VERSION 5.8 ;
BUSBITCHARS "[]" ;
DIVIDERCHAR "/" ;
 
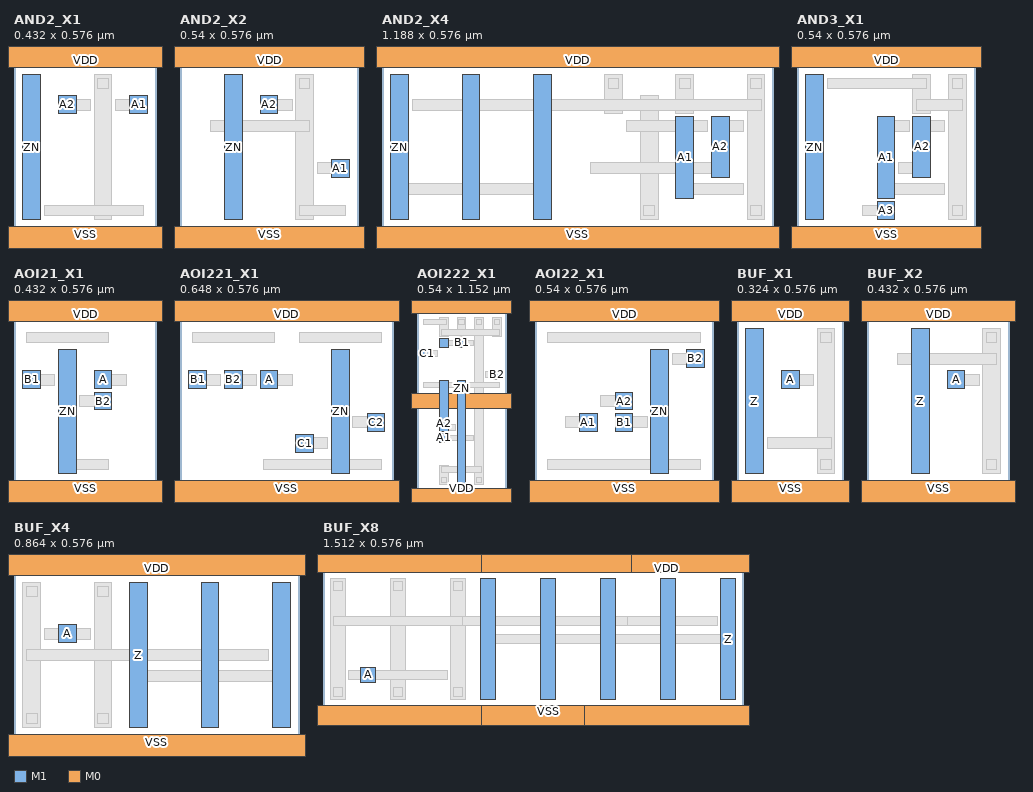
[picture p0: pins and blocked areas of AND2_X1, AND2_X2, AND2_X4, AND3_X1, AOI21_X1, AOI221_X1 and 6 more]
MACRO AND2_X1
  CLASS CORE ;
  FOREIGN AND2_X1 0 0 ;
  SIZE 0.432 BY 0.576 ;
  ORIGIN 0.0 0.0 ;
  SYMMETRY X Y ;
  PIN A1
    DIRECTION INPUT ;
    USE SIGNAL ;
    ANTENNAGATEAREA 0.005280 ;
    PORT
      LAYER M1 ;
        RECT 0.351 0.389 0.405 0.443 ;
    END
  END A1
  PIN A2
    DIRECTION INPUT ;
    USE SIGNAL ;
    ANTENNAGATEAREA 0.005280 ;
    PORT
      LAYER M1 ;
        RECT 0.135 0.389 0.189 0.443 ;
    END
  END A2
  PIN ZN
    DIRECTION OUTPUT ;
    USE SIGNAL ;
    ANTENNADIFFAREA 0.02064 ;
    PORT
      LAYER M1 ;
        RECT 0.027 0.069 0.081 0.507 ;
    END
  END ZN
  PIN VDD
    DIRECTION INOUT ;
    USE POWER ;
    PORT
      LAYER M0 ;
        RECT -0.031 0.528 0.463 0.624 ;
    END
  END VDD
  PIN VSS
    DIRECTION INOUT ;
    USE GROUND ;
    PORT
      LAYER M0 ;
        RECT -0.031 -0.048 0.463 0.048 ;
    END
  END VSS
  OBS
    LAYER M1 ;
      RECT 0.243 0.069 0.297 0.507 ;
    LAYER M0 ;
      RECT 0.092 0.08 0.394 0.112 ;
      RECT 0.254 0.464 0.286 0.496 ;
      RECT 0.308 0.4 0.394 0.432 ;
      RECT 0.146 0.4 0.232 0.432 ;
      RECT 0.038 0.464 0.07 0.496 ;
      RECT 0.038 0.08 0.07 0.112 ;
  END
END AND2_X1

MACRO AND2_X2
  CLASS CORE ;
  FOREIGN AND2_X2 0 0 ;
  SIZE 0.54 BY 0.576 ;
  ORIGIN 0.0 0.0 ;
  SYMMETRY X Y ;
  PIN A1
    DIRECTION INPUT ;
    USE SIGNAL ;
    ANTENNAGATEAREA 0.005280 ;
    PORT
      LAYER M1 ;
        RECT 0.459 0.197 0.513 0.251 ;
    END
  END A1
  PIN A2
    DIRECTION INPUT ;
    USE SIGNAL ;
    ANTENNAGATEAREA 0.005280 ;
    PORT
      LAYER M1 ;
        RECT 0.243 0.389 0.297 0.443 ;
    END
  END A2
  PIN ZN
    DIRECTION OUTPUT ;
    USE SIGNAL ;
    ANTENNADIFFAREA 0.02064 ;
    PORT
      LAYER M1 ;
        RECT 0.135 0.069 0.189 0.507 ;
    END
  END ZN
  PIN VDD
    DIRECTION INOUT ;
    USE POWER ;
    PORT
      LAYER M0 ;
        RECT -0.031 0.528 0.571 0.624 ;
    END
  END VDD
  PIN VSS
    DIRECTION INOUT ;
    USE GROUND ;
    PORT
      LAYER M0 ;
        RECT -0.031 -0.048 0.571 0.048 ;
    END
  END VSS
  OBS
    LAYER M1 ;
      RECT 0.351 0.069 0.405 0.507 ;
    LAYER M0 ;
      RECT 0.092 0.336 0.394 0.368 ;
      RECT 0.362 0.08 0.502 0.112 ;
      RECT 0.362 0.464 0.394 0.496 ;
      RECT 0.416 0.208 0.502 0.24 ;
      RECT 0.254 0.4 0.34 0.432 ;
      RECT 0.146 0.464 0.178 0.496 ;
      RECT 0.146 0.08 0.178 0.112 ;
  END
END AND2_X2

MACRO AND2_X4
  CLASS CORE ;
  FOREIGN AND2_X4 0 0 ;
  SIZE 1.188 BY 0.576 ;
  ORIGIN 0.0 0.0 ;
  SYMMETRY X Y ;
  PIN A1
    DIRECTION INPUT ;
    USE SIGNAL ;
    ANTENNAGATEAREA 0.010560 ;
    PORT
      LAYER M1 ;
        RECT 0.891 0.133 0.945 0.379 ;
    END
  END A1
  PIN A2
    DIRECTION INPUT ;
    USE SIGNAL ;
    ANTENNAGATEAREA 0.010560 ;
    PORT
      LAYER M1 ;
        RECT 0.999 0.197 1.053 0.379 ;
    END
  END A2
  PIN ZN
    DIRECTION OUTPUT ;
    USE SIGNAL ;
    ANTENNADIFFAREA 0.06192 ;
    PORT
      LAYER M1 ;
        RECT 0.027 0.069 0.081 0.507 ;
        RECT 0.243 0.069 0.297 0.507 ;
        RECT 0.459 0.069 0.513 0.507 ;
    END
  END ZN
  PIN VDD
    DIRECTION INOUT ;
    USE POWER ;
    PORT
      LAYER M0 ;
        RECT -0.031 0.528 1.219 0.624 ;
    END
  END VDD
  PIN VSS
    DIRECTION INOUT ;
    USE GROUND ;
    PORT
      LAYER M0 ;
        RECT -0.031 -0.048 1.219 0.048 ;
    END
  END VSS
  OBS
    LAYER M1 ;
      RECT 0.675 0.389 0.729 0.507 ;
      RECT 0.783 0.069 0.837 0.443 ;
      RECT 0.891 0.389 0.945 0.507 ;
      RECT 1.107 0.069 1.161 0.507 ;
    LAYER M0 ;
      RECT 0.092 0.4 1.15 0.432 ;
      RECT 0.686 0.464 0.718 0.496 ;
      RECT 0.902 0.464 0.934 0.496 ;
      RECT 1.118 0.464 1.15 0.496 ;
      RECT 0.794 0.08 0.826 0.112 ;
      RECT 1.118 0.08 1.15 0.112 ;
      RECT 0.902 0.144 1.096 0.176 ;
      RECT 0.74 0.336 0.988 0.368 ;
      RECT 1.01 0.336 1.096 0.368 ;
      RECT 0.632 0.208 1.042 0.24 ;
      RECT 0.038 0.144 0.502 0.176 ;
      RECT 0.038 0.464 0.07 0.496 ;
      RECT 0.038 0.08 0.07 0.112 ;
      RECT 0.47 0.464 0.502 0.496 ;
      RECT 0.47 0.08 0.502 0.112 ;
      RECT 0.254 0.08 0.286 0.112 ;
      RECT 0.254 0.464 0.286 0.496 ;
  END
END AND2_X4

MACRO AND3_X1
  CLASS CORE ;
  FOREIGN AND3_X1 0 0 ;
  SIZE 0.54 BY 0.576 ;
  ORIGIN 0.0 0.0 ;
  SYMMETRY X Y ;
  PIN A1
    DIRECTION INPUT ;
    USE SIGNAL ;
    ANTENNAGATEAREA 0.005280 ;
    PORT
      LAYER M1 ;
        RECT 0.243 0.133 0.297 0.379 ;
    END
  END A1
  PIN A2
    DIRECTION INPUT ;
    USE SIGNAL ;
    ANTENNAGATEAREA 0.005280 ;
    PORT
      LAYER M1 ;
        RECT 0.351 0.197 0.405 0.379 ;
    END
  END A2
  PIN A3
    DIRECTION INPUT ;
    USE SIGNAL ;
    ANTENNAGATEAREA 0.005280 ;
    PORT
      LAYER M1 ;
        RECT 0.243 0.069 0.297 0.123 ;
    END
  END A3
  PIN ZN
    DIRECTION OUTPUT ;
    USE SIGNAL ;
    ANTENNADIFFAREA 0.02064 ;
    PORT
      LAYER M1 ;
        RECT 0.027 0.069 0.081 0.507 ;
    END
  END ZN
  PIN VDD
    DIRECTION INOUT ;
    USE POWER ;
    PORT
      LAYER M0 ;
        RECT -0.031 0.528 0.571 0.624 ;
    END
  END VDD
  PIN VSS
    DIRECTION INOUT ;
    USE GROUND ;
    PORT
      LAYER M0 ;
        RECT -0.031 -0.048 0.571 0.048 ;
    END
  END VSS
  OBS
    LAYER M1 ;
      RECT 0.351 0.389 0.405 0.507 ;
      RECT 0.459 0.069 0.513 0.507 ;
    LAYER M0 ;
      RECT 0.092 0.464 0.394 0.496 ;
      RECT 0.362 0.4 0.502 0.432 ;
      RECT 0.47 0.464 0.502 0.496 ;
      RECT 0.47 0.08 0.502 0.112 ;
      RECT 0.254 0.144 0.448 0.176 ;
      RECT 0.254 0.336 0.34 0.368 ;
      RECT 0.308 0.208 0.394 0.24 ;
      RECT 0.362 0.336 0.448 0.368 ;
      RECT 0.2 0.08 0.286 0.112 ;
      RECT 0.038 0.464 0.07 0.496 ;
      RECT 0.038 0.08 0.07 0.112 ;
  END
END AND3_X1

MACRO AOI21_X1
  CLASS CORE ;
  FOREIGN AOI21_X1 0 0 ;
  SIZE 0.432 BY 0.576 ;
  ORIGIN 0.0 0.0 ;
  SYMMETRY X Y ;
  PIN A
    DIRECTION INPUT ;
    USE SIGNAL ;
    ANTENNAGATEAREA 0.005280 ;
    PORT
      LAYER M1 ;
        RECT 0.243 0.325 0.297 0.379 ;
    END
  END A
  PIN B1
    DIRECTION INPUT ;
    USE SIGNAL ;
    ANTENNAGATEAREA 0.005280 ;
    PORT
      LAYER M1 ;
        RECT 0.027 0.325 0.081 0.379 ;
    END
  END B1
  PIN B2
    DIRECTION INPUT ;
    USE SIGNAL ;
    ANTENNAGATEAREA 0.005280 ;
    PORT
      LAYER M1 ;
        RECT 0.243 0.261 0.297 0.315 ;
    END
  END B2
  PIN ZN
    DIRECTION OUTPUT ;
    USE SIGNAL ;
    ANTENNADIFFAREA 0.02064 ;
    PORT
      LAYER M1 ;
        RECT 0.135 0.069 0.189 0.443 ;
    END
  END ZN
  PIN VDD
    DIRECTION INOUT ;
    USE POWER ;
    PORT
      LAYER M0 ;
        RECT -0.031 0.528 0.463 0.624 ;
    END
  END VDD
  PIN VSS
    DIRECTION INOUT ;
    USE GROUND ;
    PORT
      LAYER M0 ;
        RECT -0.031 -0.048 0.463 0.048 ;
    END
  END VSS
  OBS
    LAYER M0 ;
      RECT 0.038 0.464 0.286 0.496 ;
      RECT 0.254 0.336 0.34 0.368 ;
      RECT 0.038 0.336 0.124 0.368 ;
      RECT 0.2 0.272 0.286 0.304 ;
      RECT 0.146 0.08 0.286 0.112 ;
      RECT 0.146 0.4 0.178 0.432 ;
  END
END AOI21_X1

MACRO AOI221_X1
  CLASS CORE ;
  FOREIGN AOI221_X1 0 0 ;
  SIZE 0.648 BY 0.576 ;
  ORIGIN 0.0 0.0 ;
  SYMMETRY X Y ;
  PIN A
    DIRECTION INPUT ;
    USE SIGNAL ;
    ANTENNAGATEAREA 0.005280 ;
    PORT
      LAYER M1 ;
        RECT 0.243 0.325 0.297 0.379 ;
    END
  END A
  PIN B1
    DIRECTION INPUT ;
    USE SIGNAL ;
    ANTENNAGATEAREA 0.005280 ;
    PORT
      LAYER M1 ;
        RECT 0.027 0.325 0.081 0.379 ;
    END
  END B1
  PIN B2
    DIRECTION INPUT ;
    USE SIGNAL ;
    ANTENNAGATEAREA 0.005280 ;
    PORT
      LAYER M1 ;
        RECT 0.135 0.325 0.189 0.379 ;
    END
  END B2
  PIN C1
    DIRECTION INPUT ;
    USE SIGNAL ;
    ANTENNAGATEAREA 0.005280 ;
    PORT
      LAYER M1 ;
        RECT 0.351 0.133 0.405 0.187 ;
    END
  END C1
  PIN C2
    DIRECTION INPUT ;
    USE SIGNAL ;
    ANTENNAGATEAREA 0.005280 ;
    PORT
      LAYER M1 ;
        RECT 0.567 0.197 0.621 0.251 ;
    END
  END C2
  PIN ZN
    DIRECTION OUTPUT ;
    USE SIGNAL ;
    ANTENNADIFFAREA 0.03096 ;
    PORT
      LAYER M1 ;
        RECT 0.459 0.069 0.513 0.443 ;
    END
  END ZN
  PIN VDD
    DIRECTION INOUT ;
    USE POWER ;
    PORT
      LAYER M0 ;
        RECT -0.031 0.528 0.679 0.624 ;
    END
  END VDD
  PIN VSS
    DIRECTION INOUT ;
    USE GROUND ;
    PORT
      LAYER M0 ;
        RECT -0.031 -0.048 0.679 0.048 ;
    END
  END VSS
  OBS
    LAYER M0 ;
      RECT 0.362 0.464 0.61 0.496 ;
      RECT 0.038 0.464 0.286 0.496 ;
      RECT 0.254 0.336 0.34 0.368 ;
      RECT 0.038 0.336 0.124 0.368 ;
      RECT 0.146 0.336 0.232 0.368 ;
      RECT 0.362 0.144 0.448 0.176 ;
      RECT 0.524 0.208 0.61 0.24 ;
      RECT 0.254 0.08 0.61 0.112 ;
      RECT 0.47 0.4 0.502 0.432 ;
  END
END AOI221_X1

MACRO AOI222_X1
  CLASS CORE ;
  FOREIGN AOI222_X1 0 0 ;
  SIZE 0.54 BY 1.152 ;
  ORIGIN 0.0 0.0 ;
  SYMMETRY X Y ;
  PIN A1
    DIRECTION INPUT ;
    USE SIGNAL ;
    ANTENNAGATEAREA 0.005280 ;
    PORT
      LAYER M1 ;
        RECT 0.135 0.325 0.189 0.379 ;
    END
  END A1
  PIN A2
    DIRECTION INPUT ;
    USE SIGNAL ;
    ANTENNAGATEAREA 0.005280 ;
    PORT
      LAYER M1 ;
        RECT 0.135 0.389 0.189 0.443 ;
    END
  END A2
  PIN B1
    DIRECTION INPUT ;
    USE SIGNAL ;
    ANTENNAGATEAREA 0.005280 ;
    PORT
      LAYER M1 ;
        RECT 0.243 0.901 0.297 0.955 ;
    END
  END B1
  PIN B2
    DIRECTION INPUT ;
    USE SIGNAL ;
    ANTENNAGATEAREA 0.005280 ;
    PORT
      LAYER M1 ;
        RECT 0.459 0.709 0.513 0.763 ;
    END
  END B2
  PIN C1
    DIRECTION INPUT ;
    USE SIGNAL ;
    ANTENNAGATEAREA 0.005280 ;
    PORT
      LAYER M1 ;
        RECT 0.027 0.837 0.081 0.891 ;
    END
  END C1
  PIN C2
    DIRECTION INPUT ;
    USE SIGNAL ;
    ANTENNAGATEAREA 0.005280 ;
    PORT
      LAYER M1 ;
        RECT 0.135 0.901 0.189 0.955 ;
    END
  END C2
  PIN ZN
    DIRECTION OUTPUT ;
    USE SIGNAL ;
    ANTENNADIFFAREA 0.04128 ;
    PORT
      LAYER M1 ;
        RECT 0.135 0.453 0.189 0.699 ;
        RECT 0.243 0.069 0.297 0.699 ;
    END
  END ZN
  PIN VDD
    DIRECTION INOUT ;
    USE POWER ;
    PORT
      LAYER M0 ;
        RECT -0.031 -0.048 0.571 0.048 ;
        RECT -0.031 1.104 0.571 1.2 ;
    END
  END VDD
  PIN VSS
    DIRECTION INOUT ;
    USE GROUND ;
    PORT
      LAYER M0 ;
        RECT -0.031 0.528 0.571 0.624 ;
    END
  END VSS
  OBS
    LAYER M1 ;
      RECT 0.459 0.965 0.513 1.083 ;
      RECT 0.243 0.965 0.297 1.083 ;
      RECT 0.135 0.965 0.189 1.083 ;
      RECT 0.351 0.069 0.405 1.083 ;
      RECT 0.135 0.069 0.189 0.187 ;
    LAYER M0 ;
      RECT 0.47 1.04 0.502 1.072 ;
      RECT 0.254 1.04 0.286 1.072 ;
      RECT 0.362 0.08 0.394 0.112 ;
      RECT 0.146 0.08 0.178 0.112 ;
      RECT 0.362 1.04 0.394 1.072 ;
      RECT 0.146 0.976 0.502 1.008 ;
      RECT 0.038 1.04 0.178 1.072 ;
      RECT 0.146 0.144 0.394 0.176 ;
      RECT 0.146 0.336 0.34 0.368 ;
      RECT 0.146 0.4 0.232 0.432 ;
      RECT 0.254 0.912 0.34 0.944 ;
      RECT 0.416 0.72 0.502 0.752 ;
      RECT 0.038 0.848 0.124 0.88 ;
      RECT 0.146 0.912 0.232 0.944 ;
      RECT 0.146 0.464 0.178 0.496 ;
      RECT 0.038 0.656 0.502 0.688 ;
      RECT 0.254 0.08 0.286 0.112 ;
  END
END AOI222_X1

MACRO AOI22_X1
  CLASS CORE ;
  FOREIGN AOI22_X1 0 0 ;
  SIZE 0.54 BY 0.576 ;
  ORIGIN 0.0 0.0 ;
  SYMMETRY X Y ;
  PIN A1
    DIRECTION INPUT ;
    USE SIGNAL ;
    ANTENNAGATEAREA 0.005280 ;
    PORT
      LAYER M1 ;
        RECT 0.135 0.197 0.189 0.251 ;
    END
  END A1
  PIN A2
    DIRECTION INPUT ;
    USE SIGNAL ;
    ANTENNAGATEAREA 0.005280 ;
    PORT
      LAYER M1 ;
        RECT 0.243 0.261 0.297 0.315 ;
    END
  END A2
  PIN B1
    DIRECTION INPUT ;
    USE SIGNAL ;
    ANTENNAGATEAREA 0.005280 ;
    PORT
      LAYER M1 ;
        RECT 0.243 0.197 0.297 0.251 ;
    END
  END B1
  PIN B2
    DIRECTION INPUT ;
    USE SIGNAL ;
    ANTENNAGATEAREA 0.005280 ;
    PORT
      LAYER M1 ;
        RECT 0.459 0.389 0.513 0.443 ;
    END
  END B2
  PIN ZN
    DIRECTION OUTPUT ;
    USE SIGNAL ;
    ANTENNADIFFAREA 0.03096 ;
    PORT
      LAYER M1 ;
        RECT 0.351 0.069 0.405 0.443 ;
    END
  END ZN
  PIN VDD
    DIRECTION INOUT ;
    USE POWER ;
    PORT
      LAYER M0 ;
        RECT -0.031 0.528 0.571 0.624 ;
    END
  END VDD
  PIN VSS
    DIRECTION INOUT ;
    USE GROUND ;
    PORT
      LAYER M0 ;
        RECT -0.031 -0.048 0.571 0.048 ;
    END
  END VSS
  OBS
    LAYER M0 ;
      RECT 0.038 0.464 0.502 0.496 ;
      RECT 0.092 0.208 0.178 0.24 ;
      RECT 0.2 0.272 0.286 0.304 ;
      RECT 0.254 0.208 0.34 0.24 ;
      RECT 0.416 0.4 0.502 0.432 ;
      RECT 0.038 0.08 0.502 0.112 ;
      RECT 0.362 0.4 0.394 0.432 ;
  END
END AOI22_X1

MACRO BUF_X1
  CLASS CORE ;
  FOREIGN BUF_X1 0 0 ;
  SIZE 0.324 BY 0.576 ;
  ORIGIN 0.0 0.0 ;
  SYMMETRY X Y ;
  PIN A
    DIRECTION INPUT ;
    USE SIGNAL ;
    ANTENNAGATEAREA 0.005280 ;
    PORT
      LAYER M1 ;
        RECT 0.135 0.325 0.189 0.379 ;
    END
  END A
  PIN Z
    DIRECTION OUTPUT ;
    USE SIGNAL ;
    ANTENNADIFFAREA 0.02064 ;
    PORT
      LAYER M1 ;
        RECT 0.027 0.069 0.081 0.507 ;
    END
  END Z
  PIN VDD
    DIRECTION INOUT ;
    USE POWER ;
    PORT
      LAYER M0 ;
        RECT -0.031 0.528 0.355 0.624 ;
    END
  END VDD
  PIN VSS
    DIRECTION INOUT ;
    USE GROUND ;
    PORT
      LAYER M0 ;
        RECT -0.031 -0.048 0.355 0.048 ;
    END
  END VSS
  OBS
    LAYER M1 ;
      RECT 0.243 0.069 0.297 0.507 ;
    LAYER M0 ;
      RECT 0.092 0.144 0.286 0.176 ;
      RECT 0.254 0.464 0.286 0.496 ;
      RECT 0.254 0.08 0.286 0.112 ;
      RECT 0.146 0.336 0.232 0.368 ;
      RECT 0.038 0.464 0.07 0.496 ;
      RECT 0.038 0.08 0.07 0.112 ;
  END
END BUF_X1

MACRO BUF_X2
  CLASS CORE ;
  FOREIGN BUF_X2 0 0 ;
  SIZE 0.432 BY 0.576 ;
  ORIGIN 0.0 0.0 ;
  SYMMETRY X Y ;
  PIN A
    DIRECTION INPUT ;
    USE SIGNAL ;
    ANTENNAGATEAREA 0.005280 ;
    PORT
      LAYER M1 ;
        RECT 0.243 0.325 0.297 0.379 ;
    END
  END A
  PIN Z
    DIRECTION OUTPUT ;
    USE SIGNAL ;
    ANTENNADIFFAREA 0.02064 ;
    PORT
      LAYER M1 ;
        RECT 0.135 0.069 0.189 0.507 ;
    END
  END Z
  PIN VDD
    DIRECTION INOUT ;
    USE POWER ;
    PORT
      LAYER M0 ;
        RECT -0.031 0.528 0.463 0.624 ;
    END
  END VDD
  PIN VSS
    DIRECTION INOUT ;
    USE GROUND ;
    PORT
      LAYER M0 ;
        RECT -0.031 -0.048 0.463 0.048 ;
    END
  END VSS
  OBS
    LAYER M1 ;
      RECT 0.351 0.069 0.405 0.507 ;
    LAYER M0 ;
      RECT 0.092 0.4 0.394 0.432 ;
      RECT 0.362 0.464 0.394 0.496 ;
      RECT 0.362 0.08 0.394 0.112 ;
      RECT 0.254 0.336 0.34 0.368 ;
      RECT 0.146 0.464 0.178 0.496 ;
      RECT 0.146 0.08 0.178 0.112 ;
  END
END BUF_X2

MACRO BUF_X4
  CLASS CORE ;
  FOREIGN BUF_X4 0 0 ;
  SIZE 0.864 BY 0.576 ;
  ORIGIN 0.0 0.0 ;
  SYMMETRY X Y ;
  PIN A
    DIRECTION INPUT ;
    USE SIGNAL ;
    ANTENNAGATEAREA 0.010560 ;
    PORT
      LAYER M1 ;
        RECT 0.135 0.325 0.189 0.379 ;
    END
  END A
  PIN Z
    DIRECTION OUTPUT ;
    USE SIGNAL ;
    ANTENNADIFFAREA 0.06192 ;
    PORT
      LAYER M1 ;
        RECT 0.351 0.069 0.405 0.507 ;
        RECT 0.783 0.069 0.837 0.507 ;
        RECT 0.567 0.069 0.621 0.507 ;
    END
  END Z
  PIN VDD
    DIRECTION INOUT ;
    USE POWER ;
    PORT
      LAYER M0 ;
        RECT -0.031 0.528 0.895 0.624 ;
    END
  END VDD
  PIN VSS
    DIRECTION INOUT ;
    USE GROUND ;
    PORT
      LAYER M0 ;
        RECT -0.031 -0.048 0.895 0.048 ;
    END
  END VSS
  OBS
    LAYER M1 ;
      RECT 0.027 0.069 0.081 0.507 ;
      RECT 0.243 0.069 0.297 0.507 ;
    LAYER M0 ;
      RECT 0.038 0.272 0.772 0.304 ;
      RECT 0.038 0.464 0.07 0.496 ;
      RECT 0.254 0.464 0.286 0.496 ;
      RECT 0.038 0.08 0.07 0.112 ;
      RECT 0.254 0.08 0.286 0.112 ;
      RECT 0.092 0.336 0.232 0.368 ;
      RECT 0.362 0.08 0.394 0.112 ;
      RECT 0.362 0.464 0.394 0.496 ;
      RECT 0.362 0.208 0.826 0.24 ;
      RECT 0.578 0.464 0.61 0.496 ;
      RECT 0.578 0.08 0.61 0.112 ;
      RECT 0.794 0.464 0.826 0.496 ;
      RECT 0.794 0.08 0.826 0.112 ;
  END
END BUF_X4

MACRO BUF_X8
  CLASS CORE ;
  FOREIGN BUF_X8 0 0 ;
  SIZE 1.512 BY 0.576 ;
  ORIGIN 0.0 0.0 ;
  SYMMETRY X Y ;
  PIN A
    DIRECTION INPUT ;
    USE SIGNAL ;
    ANTENNAGATEAREA 0.021120 ;
    PORT
      LAYER M1 ;
        RECT 0.135 0.133 0.189 0.187 ;
    END
  END A
  PIN Z
    DIRECTION OUTPUT ;
    USE SIGNAL ;
    ANTENNADIFFAREA 0.10320 ;
    PORT
      LAYER M1 ;
        RECT 1.431 0.069 1.485 0.507 ;
        RECT 0.999 0.069 1.053 0.507 ;
        RECT 1.215 0.069 1.269 0.507 ;
        RECT 0.783 0.069 0.837 0.507 ;
        RECT 0.567 0.069 0.621 0.507 ;
    END
  END Z
  PIN VDD
    DIRECTION INOUT ;
    USE POWER ;
    PORT
      LAYER M0 ;
        RECT 0.941 0.528 1.543 0.624 ;
        RECT 0.509 0.528 1.111 0.624 ;
        RECT -0.031 0.528 0.571 0.624 ;
    END
  END VDD
  PIN VSS
    DIRECTION INOUT ;
    USE GROUND ;
    PORT
      LAYER M0 ;
        RECT 0.509 -0.048 1.111 0.048 ;
        RECT 0.941 -0.048 1.543 0.048 ;
        RECT -0.031 -0.048 0.571 0.048 ;
    END
  END VSS
  OBS
    LAYER M1 ;
      RECT 0.459 0.069 0.513 0.507 ;
      RECT 0.243 0.069 0.297 0.507 ;
      RECT 0.027 0.069 0.081 0.507 ;
    LAYER M0 ;
      RECT 1.064 0.336 1.42 0.368 ;
      RECT 0.464 0.336 1.097 0.368 ;
      RECT 0.47 0.08 0.502 0.112 ;
      RECT 0.254 0.08 0.286 0.112 ;
      RECT 0.038 0.08 0.07 0.112 ;
      RECT 0.47 0.464 0.502 0.496 ;
      RECT 0.254 0.464 0.286 0.496 ;
      RECT 0.038 0.464 0.07 0.496 ;
      RECT 0.038 0.336 0.502 0.368 ;
      RECT 0.092 0.144 0.448 0.176 ;
      RECT 1.442 0.08 1.474 0.112 ;
      RECT 1.442 0.464 1.474 0.496 ;
      RECT 1.01 0.272 1.474 0.304 ;
      RECT 0.578 0.272 1.042 0.304 ;
      RECT 1.226 0.464 1.258 0.496 ;
      RECT 1.01 0.08 1.042 0.112 ;
      RECT 0.794 0.464 0.826 0.496 ;
      RECT 0.578 0.464 0.61 0.496 ;
      RECT 1.01 0.464 1.042 0.496 ;
      RECT 0.794 0.08 0.826 0.112 ;
      RECT 1.226 0.08 1.258 0.112 ;
      RECT 0.578 0.08 0.61 0.112 ;
  END
END BUF_X8

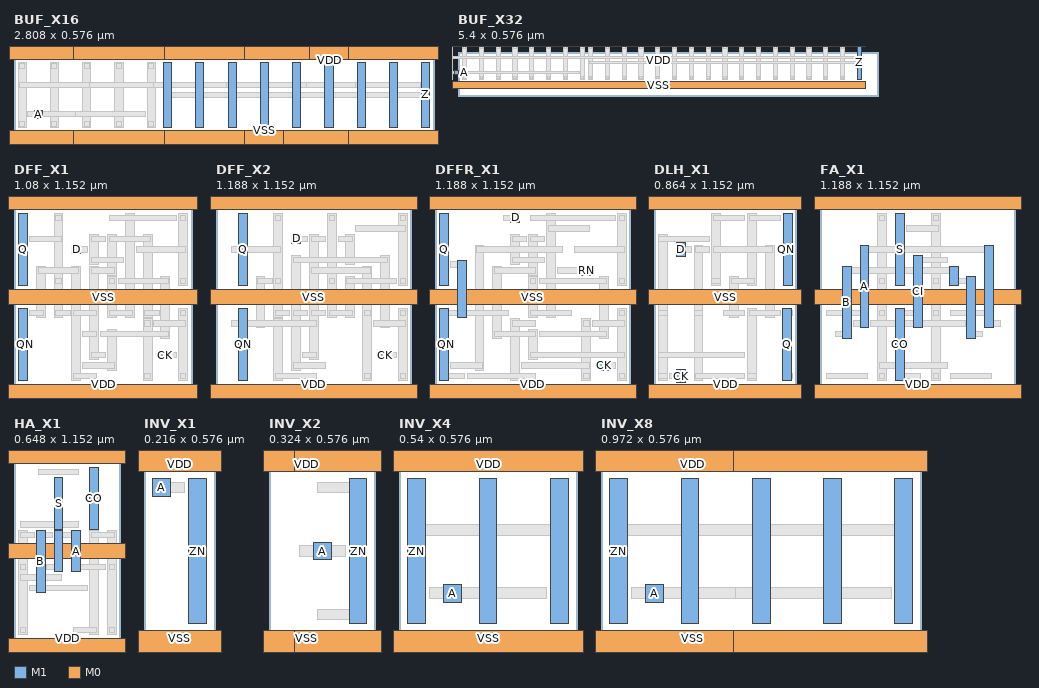
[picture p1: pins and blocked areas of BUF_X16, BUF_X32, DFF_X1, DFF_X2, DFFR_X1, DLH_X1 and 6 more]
MACRO BUF_X16
  CLASS CORE ;
  FOREIGN BUF_X16 0 0 ;
  SIZE 2.808 BY 0.576 ;
  ORIGIN 0.0 0.0 ;
  SYMMETRY X Y ;
  PIN A
    DIRECTION INPUT ;
    USE SIGNAL ;
    ANTENNAGATEAREA 0.042240 ;
    PORT
      LAYER M1 ;
        RECT 0.135 0.133 0.189 0.187 ;
    END
  END A
  PIN Z
    DIRECTION OUTPUT ;
    USE SIGNAL ;
    ANTENNADIFFAREA 0.18576 ;
    PORT
      LAYER M1 ;
        RECT 2.727 0.069 2.781 0.507 ;
        RECT 1.431 0.069 1.485 0.507 ;
        RECT 2.511 0.069 2.565 0.507 ;
        RECT 2.295 0.069 2.349 0.507 ;
        RECT 1.215 0.069 1.269 0.507 ;
        RECT 0.999 0.069 1.053 0.507 ;
        RECT 1.863 0.069 1.917 0.507 ;
        RECT 1.647 0.069 1.701 0.507 ;
        RECT 2.079 0.069 2.133 0.507 ;
    END
  END Z
  PIN VDD
    DIRECTION INOUT ;
    USE POWER ;
    PORT
      LAYER M0 ;
        RECT 1.805 0.528 2.407 0.624 ;
        RECT 2.237 0.528 2.839 0.624 ;
        RECT 1.373 0.528 1.975 0.624 ;
        RECT 0.941 0.528 1.543 0.624 ;
        RECT -0.031 0.528 0.571 0.624 ;
        RECT 0.401 0.528 1.003 0.624 ;
    END
  END VDD
  PIN VSS
    DIRECTION INOUT ;
    USE GROUND ;
    PORT
      LAYER M0 ;
        RECT 2.237 -0.048 2.839 0.048 ;
        RECT 1.373 -0.048 1.975 0.048 ;
        RECT 0.401 -0.048 1.003 0.048 ;
        RECT 1.805 -0.048 2.407 0.048 ;
        RECT 0.941 -0.048 1.543 0.048 ;
        RECT -0.031 -0.048 0.571 0.048 ;
    END
  END VSS
  OBS
    LAYER M1 ;
      RECT 0.891 0.069 0.945 0.507 ;
      RECT 0.675 0.069 0.729 0.507 ;
      RECT 0.459 0.069 0.513 0.507 ;
      RECT 0.243 0.069 0.297 0.507 ;
      RECT 0.027 0.069 0.081 0.507 ;
    LAYER M0 ;
      RECT 2.245 0.336 2.716 0.368 ;
      RECT 1.928 0.336 2.284 0.368 ;
      RECT 1.381 0.336 1.958 0.368 ;
      RECT 0.881 0.336 1.42 0.368 ;
      RECT 0.902 0.08 0.934 0.112 ;
      RECT 0.686 0.08 0.718 0.112 ;
      RECT 0.47 0.08 0.502 0.112 ;
      RECT 0.902 0.464 0.934 0.496 ;
      RECT 0.686 0.464 0.718 0.496 ;
      RECT 0.47 0.464 0.502 0.496 ;
      RECT 0.47 0.336 0.934 0.368 ;
      RECT 0.254 0.08 0.286 0.112 ;
      RECT 0.038 0.08 0.07 0.112 ;
      RECT 0.254 0.464 0.286 0.496 ;
      RECT 0.038 0.464 0.07 0.496 ;
      RECT 0.038 0.336 0.502 0.368 ;
      RECT 0.092 0.144 0.448 0.176 ;
      RECT 0.409 0.144 0.88 0.176 ;
      RECT 2.738 0.08 2.77 0.112 ;
      RECT 1.874 0.272 2.338 0.304 ;
      RECT 2.738 0.464 2.77 0.496 ;
      RECT 1.01 0.272 1.474 0.304 ;
      RECT 1.442 0.272 1.906 0.304 ;
      RECT 2.306 0.272 2.77 0.304 ;
      RECT 1.658 0.464 1.69 0.496 ;
      RECT 1.874 0.464 1.906 0.496 ;
      RECT 1.226 0.464 1.258 0.496 ;
      RECT 1.01 0.08 1.042 0.112 ;
      RECT 1.442 0.464 1.474 0.496 ;
      RECT 1.442 0.08 1.474 0.112 ;
      RECT 2.522 0.08 2.554 0.112 ;
      RECT 2.306 0.464 2.338 0.496 ;
      RECT 2.522 0.464 2.554 0.496 ;
      RECT 1.874 0.08 1.906 0.112 ;
      RECT 1.658 0.08 1.69 0.112 ;
      RECT 2.09 0.464 2.122 0.496 ;
      RECT 1.01 0.464 1.042 0.496 ;
      RECT 1.226 0.08 1.258 0.112 ;
      RECT 2.306 0.08 2.338 0.112 ;
      RECT 2.09 0.08 2.122 0.112 ;
  END
END BUF_X16


MACRO BUF_X32
  CLASS CORE ;
  ORIGIN 0 0 ;
  FOREIGN BUF_X32 0 0 ;
  SIZE 5.4 BY 0.576 ;
  PIN VDD
    DIRECTION INOUT ;
    USE POWER ;
    PORT
      LAYER M0 ;
        RECT -0.217 0.669 5.245 0.765 ;
    END
  END VDD
  PIN VSS
    DIRECTION INOUT ;
    USE GROUND ;
    PORT
      LAYER M0 ;
        RECT -0.217 0.093 5.245 0.189 ;
    END
  END VSS
  PIN A
    DIRECTION INOUT ;
    USE SIGNAL ;
    PORT
      LAYER M1 ;
        RECT -0.051 0.274 0.003 0.328 ;
    END
  END A
  PIN Z
    DIRECTION INOUT ;
    USE SIGNAL ;
    PORT
      LAYER M1 ;
        RECT 5.133 0.21 5.187 0.648 ;
    END
  END Z
  OBS
    LAYER M1 SPACING 0 ;
      RECT -0.159 0.21 -0.105 0.648 ;
      RECT 0.057 0.21 0.111 0.648 ;
      RECT 0.273 0.21 0.327 0.648 ;
      RECT 0.489 0.21 0.543 0.648 ;
      RECT 0.705 0.21 0.759 0.648 ;
      RECT 0.921 0.21 0.975 0.648 ;
      RECT 1.137 0.21 1.191 0.648 ;
      RECT 1.353 0.21 1.407 0.648 ;
      RECT 1.569 0.21 1.623 0.648 ;
      RECT 1.677 0.21 1.731 0.648 ;
      RECT 1.893 0.21 1.947 0.648 ;
      RECT 2.109 0.21 2.163 0.648 ;
      RECT 2.325 0.21 2.379 0.648 ;
      RECT 2.541 0.21 2.595 0.648 ;
      RECT 2.757 0.21 2.811 0.648 ;
      RECT 2.973 0.21 3.027 0.648 ;
      RECT 3.189 0.21 3.243 0.648 ;
      RECT 3.405 0.21 3.459 0.648 ;
      RECT 3.621 0.21 3.675 0.648 ;
      RECT 3.837 0.21 3.891 0.648 ;
      RECT 4.053 0.21 4.107 0.648 ;
      RECT 4.269 0.21 4.323 0.648 ;
      RECT 4.485 0.21 4.539 0.648 ;
      RECT 4.701 0.21 4.755 0.648 ;
      RECT 4.917 0.21 4.971 0.648 ;
    LAYER M0 SPACING 0 ;
      RECT -0.148 0.221 -0.116 0.253 ;
      RECT 0.068 0.221 0.1 0.253 ;
      RECT 0.284 0.221 0.316 0.253 ;
      RECT 0.5 0.221 0.532 0.253 ;
      RECT 0.716 0.221 0.748 0.253 ;
      RECT 0.932 0.221 0.964 0.253 ;
      RECT 1.148 0.221 1.18 0.253 ;
      RECT 1.364 0.221 1.396 0.253 ;
      RECT 1.58 0.221 1.612 0.253 ;
      RECT 1.688 0.221 1.72 0.253 ;
      RECT 1.904 0.221 1.936 0.253 ;
      RECT 2.12 0.221 2.152 0.253 ;
      RECT 2.336 0.221 2.368 0.253 ;
      RECT 2.552 0.221 2.584 0.253 ;
      RECT 2.768 0.221 2.8 0.253 ;
      RECT 2.984 0.221 3.016 0.253 ;
      RECT 3.2 0.221 3.232 0.253 ;
      RECT 3.416 0.221 3.448 0.253 ;
      RECT 3.632 0.221 3.664 0.253 ;
      RECT 3.848 0.221 3.88 0.253 ;
      RECT 4.064 0.221 4.096 0.253 ;
      RECT 4.28 0.221 4.312 0.253 ;
      RECT 4.496 0.221 4.528 0.253 ;
      RECT 4.712 0.221 4.744 0.253 ;
      RECT 4.928 0.221 4.96 0.253 ;
      RECT 5.144 0.221 5.176 0.253 ;
      RECT -0.094 0.285 1.558 0.317 ;
      RECT 1.688 0.413 5.176 0.445 ;
      RECT -0.148 0.477 5.122 0.509 ;
      RECT -0.148 0.605 -0.116 0.637 ;
      RECT 0.068 0.605 0.1 0.637 ;
      RECT 0.284 0.605 0.316 0.637 ;
      RECT 0.5 0.605 0.532 0.637 ;
      RECT 0.716 0.605 0.748 0.637 ;
      RECT 0.932 0.605 0.964 0.637 ;
      RECT 1.148 0.605 1.18 0.637 ;
      RECT 1.364 0.605 1.396 0.637 ;
      RECT 1.58 0.605 1.612 0.637 ;
      RECT 1.688 0.605 1.72 0.637 ;
      RECT 1.904 0.605 1.936 0.637 ;
      RECT 2.12 0.605 2.152 0.637 ;
      RECT 2.336 0.605 2.368 0.637 ;
      RECT 2.552 0.605 2.584 0.637 ;
      RECT 2.768 0.605 2.8 0.637 ;
      RECT 2.984 0.605 3.016 0.637 ;
      RECT 3.2 0.605 3.232 0.637 ;
      RECT 3.416 0.605 3.448 0.637 ;
      RECT 3.632 0.605 3.664 0.637 ;
      RECT 3.848 0.605 3.88 0.637 ;
      RECT 4.064 0.605 4.096 0.637 ;
      RECT 4.28 0.605 4.312 0.637 ;
      RECT 4.496 0.605 4.528 0.637 ;
      RECT 4.712 0.605 4.744 0.637 ;
      RECT 4.928 0.605 4.96 0.637 ;
      RECT 5.144 0.605 5.176 0.637 ;
  END
END BUF_X32



MACRO DFF_X1
  CLASS CORE ;
  FOREIGN DFF_X1 0 0 ;
  SIZE 1.08 BY 1.152 ;
  ORIGIN 0.0 0.0 ;
  SYMMETRY X Y ;
  PIN CK
    DIRECTION INPUT ;
    USE CLOCK ;
    ANTENNAGATEAREA 0.005280 ;
    PORT
      LAYER M1 ;
        RECT 0.891 0.197 0.945 0.251 ;
    END
  END CK
  PIN D
    DIRECTION INPUT ;
    USE SIGNAL ;
    ANTENNAGATEAREA 0.005280 ;
    PORT
      LAYER M1 ;
        RECT 0.351 0.837 0.405 0.891 ;
    END
  END D
  PIN Q
    DIRECTION OUTPUT ;
    USE SIGNAL ;
    ANTENNADIFFAREA 0.02064 ;
    PORT
      LAYER M1 ;
        RECT 0.027 0.645 0.081 1.083 ;
    END
  END Q
  PIN QN
    DIRECTION OUTPUT ;
    USE SIGNAL ;
    ANTENNADIFFAREA 0.02064 ;
    PORT
      LAYER M1 ;
        RECT 0.027 0.069 0.081 0.507 ;
    END
  END QN
  PIN VDD
    DIRECTION INOUT ;
    USE POWER ;
    PORT
      LAYER M0 ;
        RECT -0.031 1.104 1.111 1.2 ;
        RECT -0.031 -0.048 1.111 0.048 ;
    END
  END VDD
  PIN VSS
    DIRECTION INOUT ;
    USE GROUND ;
    PORT
      LAYER M0 ;
        RECT -0.031 0.528 1.111 0.624 ;
    END
  END VSS
  OBS
    LAYER M1 ;
      RECT 0.459 0.197 0.513 0.763 ;
      RECT 0.567 0.709 0.621 0.955 ;
      RECT 0.783 0.453 0.837 0.955 ;
      RECT 0.999 0.069 1.053 0.507 ;
      RECT 0.243 0.453 0.297 1.083 ;
      RECT 0.567 0.453 0.621 0.699 ;
      RECT 0.675 0.453 0.729 1.083 ;
      RECT 0.999 0.645 1.053 1.083 ;
      RECT 0.135 0.453 0.189 0.763 ;
      RECT 0.351 0.069 0.405 0.763 ;
      RECT 0.459 0.773 0.513 0.955 ;
      RECT 0.567 0.133 0.621 0.379 ;
      RECT 0.783 0.069 0.837 0.443 ;
      RECT 0.891 0.325 0.945 0.699 ;
    LAYER M0 ;
      RECT 0.578 0.912 0.826 0.944 ;
      RECT 0.47 0.72 0.61 0.752 ;
      RECT 0.794 0.464 0.88 0.496 ;
      RECT 0.848 0.4 1.042 0.432 ;
      RECT 0.416 0.336 0.502 0.368 ;
      RECT 0.47 0.208 0.556 0.24 ;
      RECT 0.092 0.912 0.286 0.944 ;
      RECT 0.254 0.464 0.34 0.496 ;
      RECT 0.578 1.04 0.988 1.072 ;
      RECT 0.578 0.464 0.718 0.496 ;
      RECT 0.74 0.848 1.042 0.88 ;
      RECT 0.146 0.72 0.394 0.752 ;
      RECT 0.092 0.464 0.178 0.496 ;
      RECT 0.362 0.464 0.502 0.496 ;
      RECT 0.362 0.08 0.502 0.112 ;
      RECT 0.47 0.912 0.556 0.944 ;
      RECT 0.47 0.784 0.664 0.816 ;
      RECT 0.632 0.656 0.934 0.688 ;
      RECT 0.524 0.336 0.934 0.368 ;
      RECT 0.416 0.144 0.61 0.176 ;
      RECT 1.01 0.464 1.042 0.496 ;
      RECT 1.01 0.08 1.042 0.112 ;
      RECT 0.254 1.04 0.286 1.072 ;
      RECT 0.254 0.656 0.286 0.688 ;
      RECT 0.578 0.656 0.61 0.688 ;
      RECT 1.01 1.04 1.042 1.072 ;
      RECT 1.01 0.656 1.042 0.688 ;
      RECT 0.794 0.4 0.826 0.432 ;
      RECT 0.794 0.08 0.826 0.112 ;
      RECT 0.902 0.208 0.988 0.24 ;
      RECT 0.362 0.848 0.448 0.88 ;
      RECT 0.038 0.656 0.07 0.688 ;
      RECT 0.038 1.04 0.07 1.072 ;
      RECT 0.038 0.464 0.07 0.496 ;
      RECT 0.038 0.08 0.07 0.112 ;
  END
END DFF_X1

MACRO DFF_X2
  CLASS CORE ;
  FOREIGN DFF_X2 0 0 ;
  SIZE 1.188 BY 1.152 ;
  ORIGIN 0.0 0.0 ;
  SYMMETRY X Y ;
  PIN CK
    DIRECTION INPUT ;
    USE CLOCK ;
    ANTENNAGATEAREA 0.005280 ;
    PORT
      LAYER M1 ;
        RECT 0.999 0.197 1.053 0.251 ;
    END
  END CK
  PIN D
    DIRECTION INPUT ;
    USE SIGNAL ;
    ANTENNAGATEAREA 0.005280 ;
    PORT
      LAYER M1 ;
        RECT 0.459 0.901 0.513 0.955 ;
    END
  END D
  PIN Q
    DIRECTION OUTPUT ;
    USE SIGNAL ;
    ANTENNADIFFAREA 0.02064 ;
    PORT
      LAYER M1 ;
        RECT 0.135 0.645 0.189 1.083 ;
    END
  END Q
  PIN QN
    DIRECTION OUTPUT ;
    USE SIGNAL ;
    ANTENNADIFFAREA 0.02064 ;
    PORT
      LAYER M1 ;
        RECT 0.135 0.069 0.189 0.507 ;
    END
  END QN
  PIN VDD
    DIRECTION INOUT ;
    USE POWER ;
    PORT
      LAYER M0 ;
        RECT -0.031 1.104 1.219 1.2 ;
        RECT -0.031 -0.048 1.219 0.048 ;
    END
  END VDD
  PIN VSS
    DIRECTION INOUT ;
    USE GROUND ;
    PORT
      LAYER M0 ;
        RECT -0.031 0.528 1.219 0.624 ;
    END
  END VSS
  OBS
    LAYER M1 ;
      RECT 0.675 0.453 0.729 1.083 ;
      RECT 0.783 0.453 0.837 0.699 ;
      RECT 0.567 0.197 0.621 0.955 ;
      RECT 0.891 0.069 0.945 0.763 ;
      RECT 1.107 0.645 1.161 1.083 ;
      RECT 0.459 0.133 0.513 0.827 ;
      RECT 0.783 0.773 0.837 0.955 ;
      RECT 0.999 0.389 1.053 0.827 ;
      RECT 1.107 0.069 1.161 0.507 ;
      RECT 0.351 0.453 0.405 1.083 ;
      RECT 0.243 0.389 0.297 0.699 ;
      RECT 0.351 0.069 0.405 0.443 ;
    LAYER M0 ;
      RECT 0.794 0.656 1.096 0.688 ;
      RECT 0.686 0.464 0.826 0.496 ;
      RECT 0.578 0.912 0.664 0.944 ;
      RECT 0.578 0.72 0.934 0.752 ;
      RECT 0.578 0.464 0.664 0.496 ;
      RECT 0.524 0.208 0.61 0.24 ;
      RECT 0.848 0.976 1.15 1.008 ;
      RECT 0.74 0.912 0.826 0.944 ;
      RECT 0.47 0.784 1.042 0.816 ;
      RECT 0.47 0.464 0.556 0.496 ;
      RECT 0.956 0.4 1.15 0.432 ;
      RECT 0.47 0.144 0.664 0.176 ;
      RECT 0.092 0.848 0.394 0.88 ;
      RECT 0.362 0.464 0.448 0.496 ;
      RECT 0.254 0.656 0.34 0.688 ;
      RECT 0.092 0.4 0.61 0.432 ;
      RECT 0.362 0.08 0.61 0.112 ;
      RECT 0.686 1.04 0.718 1.072 ;
      RECT 0.686 0.656 0.718 0.688 ;
      RECT 0.902 0.464 0.934 0.496 ;
      RECT 0.902 0.08 0.934 0.112 ;
      RECT 1.118 1.04 1.15 1.072 ;
      RECT 1.118 0.656 1.15 0.688 ;
      RECT 1.118 0.464 1.15 0.496 ;
      RECT 1.118 0.08 1.15 0.112 ;
      RECT 0.362 1.04 0.394 1.072 ;
      RECT 0.362 0.656 0.394 0.688 ;
      RECT 1.01 0.208 1.096 0.24 ;
      RECT 0.47 0.912 0.556 0.944 ;
      RECT 0.146 0.656 0.178 0.688 ;
      RECT 0.146 1.04 0.178 1.072 ;
      RECT 0.146 0.464 0.178 0.496 ;
      RECT 0.146 0.08 0.178 0.112 ;
  END
END DFF_X2

MACRO DFFR_X1
  CLASS CORE ;
  FOREIGN DFFR_X1 0 0 ;
  SIZE 1.188 BY 1.152 ;
  ORIGIN 0.0 0.0 ;
  SYMMETRY X Y ;
  PIN CK
    DIRECTION INPUT ;
    USE CLOCK ;
    ANTENNAGATEAREA 0.005280 ;
    PORT
      LAYER M1 ;
        RECT 0.999 0.133 1.053 0.187 ;
    END
  END CK
  PIN D
    DIRECTION INPUT ;
    USE SIGNAL ;
    ANTENNAGATEAREA 0.005280 ;
    PORT
      LAYER M1 ;
        RECT 0.459 1.029 0.513 1.083 ;
    END
  END D
  PIN Q
    DIRECTION OUTPUT ;
    USE SIGNAL ;
    ANTENNADIFFAREA 0.02064 ;
    PORT
      LAYER M1 ;
        RECT 0.027 0.645 0.081 1.083 ;
    END
  END Q
  PIN QN
    DIRECTION OUTPUT ;
    USE SIGNAL ;
    ANTENNAGATEAREA 0.010560 ;
    ANTENNADIFFAREA 0.02064 ;
    PORT
      LAYER M1 ;
        RECT 0.027 0.069 0.081 0.507 ;
        RECT 0.135 0.453 0.189 0.8 ;
    END
  END QN
  PIN RN
    DIRECTION INPUT ;
    USE SIGNAL ;
    ANTENNAGATEAREA 0.005280 ;
    PORT
      LAYER M1 ;
        RECT 0.891 0.709 0.945 0.763 ;
    END
  END RN
  PIN VDD
    DIRECTION INOUT ;
    USE POWER ;
    PORT
      LAYER M0 ;
        RECT -0.031 -0.048 1.219 0.048 ;
        RECT -0.031 1.104 1.219 1.2 ;
    END
  END VDD
  PIN VSS
    DIRECTION INOUT ;
    USE GROUND ;
    PORT
      LAYER M0 ;
        RECT -0.031 0.528 1.219 0.624 ;
    END
  END VSS
  OBS
    LAYER M1 ;
      RECT 0.243 0.133 0.297 0.891 ;
      RECT 0.675 0.453 0.729 1.084 ;
      RECT 1.107 0.069 1.161 0.507 ;
      RECT 0.891 0.069 0.945 0.443 ;
      RECT 0.567 0.197 0.621 0.379 ;
      RECT 0.459 0.069 0.513 0.443 ;
      RECT 0.999 0.325 1.053 0.699 ;
      RECT 0.567 0.453 0.621 0.699 ;
      RECT 1.107 0.645 1.161 1.083 ;
      RECT 0.567 0.709 0.621 0.955 ;
      RECT 0.459 0.773 0.513 0.955 ;
      RECT 0.351 0.325 0.405 0.763 ;
    LAYER M0 ;
      RECT 0.632 0.336 1.042 0.368 ;
      RECT 0.956 0.4 1.15 0.432 ;
      RECT 0.524 0.144 0.934 0.176 ;
      RECT 0.578 0.464 0.826 0.496 ;
      RECT 0.47 0.4 0.61 0.432 ;
      RECT 0.2 0.08 0.61 0.112 ;
      RECT 0.362 0.336 0.61 0.368 ;
      RECT 0.578 0.208 1.15 0.24 ;
      RECT 1.118 0.464 1.15 0.496 ;
      RECT 1.118 0.08 1.15 0.112 ;
      RECT 0.902 0.4 0.934 0.432 ;
      RECT 0.902 0.08 0.934 0.112 ;
      RECT 0.686 0.976 0.934 1.008 ;
      RECT 0.092 0.144 0.286 0.176 ;
      RECT 0.254 0.848 0.772 0.88 ;
      RECT 0.578 1.04 1.096 1.072 ;
      RECT 0.848 0.848 1.15 0.88 ;
      RECT 0.632 0.656 1.042 0.688 ;
      RECT 0.578 0.912 0.664 0.944 ;
      RECT 0.47 0.784 0.664 0.816 ;
      RECT 0.362 0.72 0.61 0.752 ;
      RECT 0.47 0.912 0.556 0.944 ;
      RECT 0.578 0.656 0.61 0.688 ;
      RECT 1.118 1.04 1.15 1.072 ;
      RECT 1.118 0.656 1.15 0.688 ;
      RECT 1.01 0.144 1.096 0.176 ;
      RECT 0.416 1.04 0.502 1.072 ;
      RECT 0.038 0.656 0.07 0.688 ;
      RECT 0.038 1.04 0.07 1.072 ;
      RECT 0.038 0.08 0.178 0.112 ;
      RECT 0.038 0.464 0.448 0.496 ;
      RECT 0.092 0.757 0.178 0.789 ;
      RECT 0.74 0.72 0.934 0.752 ;
  END
END DFFR_X1

MACRO DLH_X1
  CLASS CORE ;
  FOREIGN DLH_X1 0 0 ;
  SIZE 0.864 BY 1.152 ;
  ORIGIN 0.0 0.0 ;
  SYMMETRY X Y ;
  PIN CK
    DIRECTION INPUT ;
    USE CLOCK ;
    ANTENNAGATEAREA 0.005280 ;
    PORT
      LAYER M1 ;
        RECT 0.135 0.055 0.189 0.137 ;
    END
  END CK
  PIN D
    DIRECTION INPUT ;
    USE SIGNAL ;
    ANTENNAGATEAREA 0.005280 ;
    PORT
      LAYER M1 ;
        RECT 0.135 0.823 0.189 0.905 ;
    END
  END D
  PIN Q
    DIRECTION OUTPUT ;
    USE SIGNAL ;
    ANTENNADIFFAREA 0.02064 ;
    PORT
      LAYER M1 ;
        RECT 0.782 0.069 0.836 0.507 ;
    END
  END Q
  PIN QN
    DIRECTION OUTPUT ;
    USE SIGNAL ;
    ANTENNADIFFAREA 0.02064 ;
    PORT
      LAYER M1 ;
        RECT 0.783 0.645 0.837 1.083 ;
    END
  END QN
  PIN VDD
    DIRECTION INOUT ;
    USE POWER ;
    PORT
      LAYER M0 ;
        RECT -0.031 1.104 0.895 1.2 ;
        RECT -0.031 -0.048 0.895 0.048 ;
    END
  END VDD
  PIN VSS
    DIRECTION INOUT ;
    USE GROUND ;
    PORT
      LAYER M0 ;
        RECT -0.031 0.528 0.895 0.624 ;
    END
  END VSS
  OBS
    LAYER M1 ;
      RECT 0.459 0.453 0.513 0.699 ;
      RECT 0.351 0.645 0.405 1.083 ;
      RECT 0.566 0.645 0.62 1.083 ;
      RECT 0.567 0.069 0.621 0.507 ;
      RECT 0.027 0.069 0.081 0.955 ;
      RECT 0.243 0.069 0.297 0.891 ;
      RECT 0.675 0.453 0.729 0.891 ;
    LAYER M0 ;
      RECT 0.362 0.848 0.718 0.88 ;
      RECT 0.254 0.848 0.335 0.88 ;
      RECT 0.027 0.08 0.081 0.112 ;
      RECT 0.027 0.912 0.335 0.944 ;
      RECT 0.567 0.08 0.621 0.112 ;
      RECT 0.254 0.08 0.551 0.112 ;
      RECT 0.421 0.464 0.551 0.496 ;
      RECT 0.027 0.208 0.551 0.24 ;
      RECT 0.351 0.656 0.405 0.688 ;
      RECT 0.243 0.464 0.297 0.496 ;
      RECT 0.362 1.04 0.551 1.072 ;
      RECT 0.578 1.04 0.767 1.072 ;
      RECT 0.47 0.656 0.61 0.688 ;
      RECT 0.027 0.464 0.081 0.496 ;
      RECT 0.578 0.464 0.767 0.496 ;
      RECT 0.097 0.08 0.178 0.112 ;
      RECT 0.146 0.848 0.227 0.88 ;
      RECT 0.783 0.464 0.837 0.496 ;
      RECT 0.783 0.08 0.837 0.112 ;
      RECT 0.783 0.656 0.837 0.688 ;
      RECT 0.783 1.04 0.837 1.072 ;
  END
END DLH_X1

MACRO FA_X1
  CLASS CORE ;
  FOREIGN FA_X1 0 0 ;
  SIZE 1.188 BY 1.152 ;
  ORIGIN 0.0 0.0 ;
  SYMMETRY X Y ;
  PIN A
    DIRECTION INPUT ;
    USE SIGNAL ;
    ANTENNAGATEAREA 0.021120 ;
    PORT
      LAYER M1 ;
        RECT 0.243 0.389 0.297 0.891 ;
        RECT 0.999 0.389 1.053 0.891 ;
    END
  END A
  PIN B
    DIRECTION INPUT ;
    USE SIGNAL ;
    ANTENNAGATEAREA 0.021120 ;
    PORT
      LAYER M1 ;
        RECT 0.135 0.325 0.189 0.763 ;
        RECT 0.783 0.645 0.837 0.763 ;
        RECT 0.891 0.325 0.945 0.699 ;
    END
  END B
  PIN CI
    DIRECTION INPUT ;
    USE SIGNAL ;
    ANTENNAGATEAREA 0.015840 ;
    PORT
      LAYER M1 ;
        RECT 0.567 0.389 0.621 0.827 ;
    END
  END CI
  PIN CO
    DIRECTION OUTPUT ;
    USE SIGNAL ;
    ANTENNADIFFAREA 0.02064 ;
    PORT
      LAYER M1 ;
        RECT 0.459 0.069 0.513 0.507 ;
    END
  END CO
  PIN S
    DIRECTION INPUT ;
    USE SIGNAL ;
    ANTENNADIFFAREA 0.02064 ;
    PORT
      LAYER M1 ;
        RECT 0.459 0.645 0.513 1.083 ;
    END
  END S
  PIN VDD
    DIRECTION INOUT ;
    USE POWER ;
    PORT
      LAYER M0 ;
        RECT -0.031 1.104 1.219 1.2 ;
        RECT -0.031 -0.048 1.219 0.048 ;
    END
  END VDD
  PIN VSS
    DIRECTION INOUT ;
    USE GROUND ;
    PORT
      LAYER M0 ;
        RECT -0.031 0.528 1.219 0.624 ;
    END
  END VSS
  OBS
    LAYER M1 ;
      RECT 0.675 0.069 0.729 1.083 ;
      RECT 0.351 0.069 0.405 1.083 ;
    LAYER M0 ;
      RECT 0.524 0.976 0.718 1.008 ;
      RECT 0.038 0.08 0.286 0.112 ;
      RECT 0.362 0.144 0.772 0.176 ;
      RECT 0.794 0.08 1.042 0.112 ;
      RECT 0.686 1.04 0.718 1.072 ;
      RECT 0.686 0.656 0.718 0.688 ;
      RECT 0.686 0.464 0.718 0.496 ;
      RECT 0.686 0.08 0.718 0.112 ;
      RECT 0.794 0.464 1.042 0.496 ;
      RECT 0.362 1.04 0.394 1.072 ;
      RECT 0.362 0.656 0.394 0.688 ;
      RECT 0.362 0.464 0.394 0.496 ;
      RECT 0.362 0.08 0.394 0.112 ;
      RECT 0.038 0.464 0.286 0.496 ;
      RECT 0.205 0.4 0.286 0.432 ;
      RECT 0.254 0.848 1.042 0.88 ;
      RECT 1.01 0.4 1.096 0.432 ;
      RECT 0.092 0.336 0.178 0.368 ;
      RECT 0.146 0.72 0.826 0.752 ;
      RECT 0.794 0.656 0.934 0.688 ;
      RECT 0.902 0.336 0.983 0.368 ;
      RECT 0.308 0.4 0.88 0.432 ;
      RECT 0.578 0.784 0.772 0.816 ;
      RECT 0.47 0.464 0.61 0.496 ;
      RECT 0.47 0.08 0.61 0.112 ;
      RECT 0.47 1.04 0.502 1.072 ;
      RECT 0.47 0.656 0.502 0.688 ;
  END
END FA_X1

MACRO HA_X1
  CLASS CORE ;
  FOREIGN HA_X1 0 0 ;
  SIZE 0.648 BY 1.152 ;
  ORIGIN 0.0 0.0 ;
  SYMMETRY X Y ;
  PIN A
    DIRECTION INPUT ;
    USE SIGNAL ;
    ANTENNAGATEAREA 0.015840 ;
    PORT
      LAYER M1 ;
        RECT 0.243 0.453 0.297 0.699 ;
        RECT 0.351 0.453 0.405 0.699 ;
    END
  END A
  PIN B
    DIRECTION INPUT ;
    USE SIGNAL ;
    ANTENNAGATEAREA 0.015840 ;
    PORT
      LAYER M1 ;
        RECT 0.135 0.325 0.189 0.699 ;
    END
  END B
  PIN CO
    DIRECTION OUTPUT ;
    USE SIGNAL ;
    ANTENNADIFFAREA 0.02064 ;
    PORT
      LAYER M1 ;
        RECT 0.459 0.709 0.513 1.083 ;
    END
  END CO
  PIN S
    DIRECTION INPUT ;
    USE SIGNAL ;
    ANTENNADIFFAREA 0.03096 ;
    PORT
      LAYER M1 ;
        RECT 0.243 0.709 0.297 1.019 ;
    END
  END S
  PIN VDD
    DIRECTION INOUT ;
    USE POWER ;
    PORT
      LAYER M0 ;
        RECT -0.031 1.104 0.679 1.2 ;
        RECT -0.031 -0.048 0.679 0.048 ;
    END
  END VDD
  PIN VSS
    DIRECTION INOUT ;
    USE GROUND ;
    PORT
      LAYER M0 ;
        RECT -0.031 0.528 0.679 0.624 ;
    END
  END VSS
  OBS
    LAYER M1 ;
      RECT 0.459 0.069 0.513 0.699 ;
      RECT 0.567 0.069 0.621 0.699 ;
      RECT 0.027 0.069 0.081 0.699 ;
    LAYER M0 ;
      RECT 0.47 0.656 0.61 0.688 ;
      RECT 0.362 0.08 0.502 0.112 ;
      RECT 0.038 0.656 0.124 0.688 ;
      RECT 0.038 0.4 0.286 0.432 ;
      RECT 0.146 1.04 0.394 1.072 ;
      RECT 0.578 0.464 0.61 0.496 ;
      RECT 0.578 0.08 0.61 0.112 ;
      RECT 0.038 0.464 0.07 0.496 ;
      RECT 0.038 0.08 0.07 0.112 ;
      RECT 0.2 0.464 0.286 0.496 ;
      RECT 0.254 0.656 0.394 0.688 ;
      RECT 0.362 0.464 0.556 0.496 ;
      RECT 0.092 0.336 0.448 0.368 ;
      RECT 0.146 0.656 0.232 0.688 ;
      RECT 0.47 0.72 0.502 0.752 ;
      RECT 0.47 1.04 0.502 1.072 ;
      RECT 0.038 0.72 0.394 0.752 ;
      RECT 0.254 0.976 0.286 1.008 ;
  END
END HA_X1

MACRO INV_X1
  CLASS CORE ;
  FOREIGN INV_X1 0 0 ;
  SIZE 0.216 BY 0.576 ;
  ORIGIN 0.0 0.0 ;
  SYMMETRY X Y ;
  PIN A
    DIRECTION INPUT ;
    USE SIGNAL ;
    ANTENNAGATEAREA 0.005280 ;
    PORT
      LAYER M1 ;
        RECT 0.027 0.453 0.081 0.507 ;
    END
  END A
  PIN ZN
    DIRECTION OUTPUT ;
    USE SIGNAL ;
    ANTENNADIFFAREA 0.02064 ;
    PORT
      LAYER M1 ;
        RECT 0.135 0.069 0.189 0.507 ;
    END
  END ZN
  PIN VDD
    DIRECTION INOUT ;
    USE POWER ;
    PORT
      LAYER M0 ;
        RECT -0.031 0.528 0.247 0.624 ;
    END
  END VDD
  PIN VSS
    DIRECTION INOUT ;
    USE GROUND ;
    PORT
      LAYER M0 ;
        RECT -0.031 -0.048 0.247 0.048 ;
    END
  END VSS
  OBS
    LAYER M0 ;
      RECT 0.038 0.464 0.124 0.496 ;
      RECT 0.146 0.464 0.178 0.496 ;
      RECT 0.146 0.08 0.178 0.112 ;
  END
END INV_X1

MACRO INV_X2
  CLASS CORE ;
  FOREIGN INV_X2 0 0 ;
  SIZE 0.324 BY 0.576 ;
  ORIGIN 0.0 0.0 ;
  SYMMETRY X Y ;
  PIN A
    DIRECTION INPUT ;
    USE SIGNAL ;
    ANTENNAGATEAREA 0.010560 ;
    PORT
      LAYER M1 ;
        RECT 0.135 0.261 0.189 0.315 ;
    END
  END A
  PIN ZN
    DIRECTION OUTPUT ;
    USE SIGNAL ;
    ANTENNADIFFAREA 0.02064 ;
    PORT
      LAYER M1 ;
        RECT 0.243 0.069 0.297 0.507 ;
    END
  END ZN
  PIN VDD
    DIRECTION INOUT ;
    USE POWER ;
    PORT
      LAYER M0 ;
        RECT -0.031 0.528 0.247 0.624 ;
        RECT 0.077 0.528 0.355 0.624 ;
    END
  END VDD
  PIN VSS
    DIRECTION INOUT ;
    USE GROUND ;
    PORT
      LAYER M0 ;
        RECT -0.031 -0.048 0.247 0.048 ;
        RECT 0.077 -0.048 0.355 0.048 ;
    END
  END VSS
  OBS
    LAYER M0 ;
      RECT 0.146 0.272 0.232 0.304 ;
      RECT 0.092 0.272 0.178 0.304 ;
      RECT 0.146 0.464 0.286 0.496 ;
      RECT 0.146 0.08 0.286 0.112 ;
  END
END INV_X2

MACRO INV_X4
  CLASS CORE ;
  FOREIGN INV_X4 0 0 ;
  SIZE 0.54 BY 0.576 ;
  ORIGIN 0.0 0.0 ;
  SYMMETRY X Y ;
  PIN A
    DIRECTION INPUT ;
    USE SIGNAL ;
    ANTENNAGATEAREA 0.021120 ;
    PORT
      LAYER M1 ;
        RECT 0.135 0.133 0.189 0.187 ;
    END
  END A
  PIN ZN
    DIRECTION OUTPUT ;
    USE SIGNAL ;
    ANTENNADIFFAREA 0.06192 ;
    PORT
      LAYER M1 ;
        RECT 0.027 0.069 0.081 0.507 ;
        RECT 0.243 0.069 0.297 0.507 ;
        RECT 0.459 0.069 0.513 0.507 ;
    END
  END ZN
  PIN VDD
    DIRECTION INOUT ;
    USE POWER ;
    PORT
      LAYER M0 ;
        RECT -0.031 0.528 0.571 0.624 ;
    END
  END VDD
  PIN VSS
    DIRECTION INOUT ;
    USE GROUND ;
    PORT
      LAYER M0 ;
        RECT -0.031 -0.048 0.571 0.048 ;
    END
  END VSS
  OBS
    LAYER M0 ;
      RECT 0.092 0.144 0.448 0.176 ;
      RECT 0.038 0.464 0.07 0.496 ;
      RECT 0.038 0.08 0.07 0.112 ;
      RECT 0.038 0.336 0.502 0.368 ;
      RECT 0.47 0.464 0.502 0.496 ;
      RECT 0.47 0.08 0.502 0.112 ;
      RECT 0.254 0.08 0.286 0.112 ;
      RECT 0.254 0.464 0.286 0.496 ;
  END
END INV_X4

MACRO INV_X8
  CLASS CORE ;
  FOREIGN INV_X8 0 0 ;
  SIZE 0.972 BY 0.576 ;
  ORIGIN 0.0 0.0 ;
  SYMMETRY X Y ;
  PIN A
    DIRECTION INPUT ;
    USE SIGNAL ;
    ANTENNAGATEAREA 0.042240 ;
    PORT
      LAYER M1 ;
        RECT 0.135 0.133 0.189 0.187 ;
    END
  END A
  PIN ZN
    DIRECTION OUTPUT ;
    USE SIGNAL ;
    ANTENNADIFFAREA 0.10320 ;
    PORT
      LAYER M1 ;
        RECT 0.027 0.069 0.081 0.507 ;
        RECT 0.243 0.069 0.297 0.507 ;
        RECT 0.675 0.069 0.729 0.507 ;
        RECT 0.891 0.069 0.945 0.507 ;
        RECT 0.459 0.069 0.513 0.507 ;
    END
  END ZN
  PIN VDD
    DIRECTION INOUT ;
    USE POWER ;
    PORT
      LAYER M0 ;
        RECT -0.031 0.528 0.571 0.624 ;
        RECT 0.401 0.528 1.003 0.624 ;
    END
  END VDD
  PIN VSS
    DIRECTION INOUT ;
    USE GROUND ;
    PORT
      LAYER M0 ;
        RECT 0.401 -0.048 1.003 0.048 ;
        RECT -0.031 -0.048 0.571 0.048 ;
    END
  END VSS
  OBS
    LAYER M0 ;
      RECT 0.092 0.144 0.448 0.176 ;
      RECT 0.409 0.144 0.88 0.176 ;
      RECT 0.47 0.336 0.934 0.368 ;
      RECT 0.038 0.464 0.07 0.496 ;
      RECT 0.038 0.08 0.07 0.112 ;
      RECT 0.038 0.336 0.502 0.368 ;
      RECT 0.47 0.08 0.502 0.112 ;
      RECT 0.47 0.464 0.502 0.496 ;
      RECT 0.686 0.464 0.718 0.496 ;
      RECT 0.254 0.08 0.286 0.112 ;
      RECT 0.902 0.464 0.934 0.496 ;
      RECT 0.686 0.08 0.718 0.112 ;
      RECT 0.254 0.464 0.286 0.496 ;
      RECT 0.902 0.08 0.934 0.112 ;
  END
END INV_X8

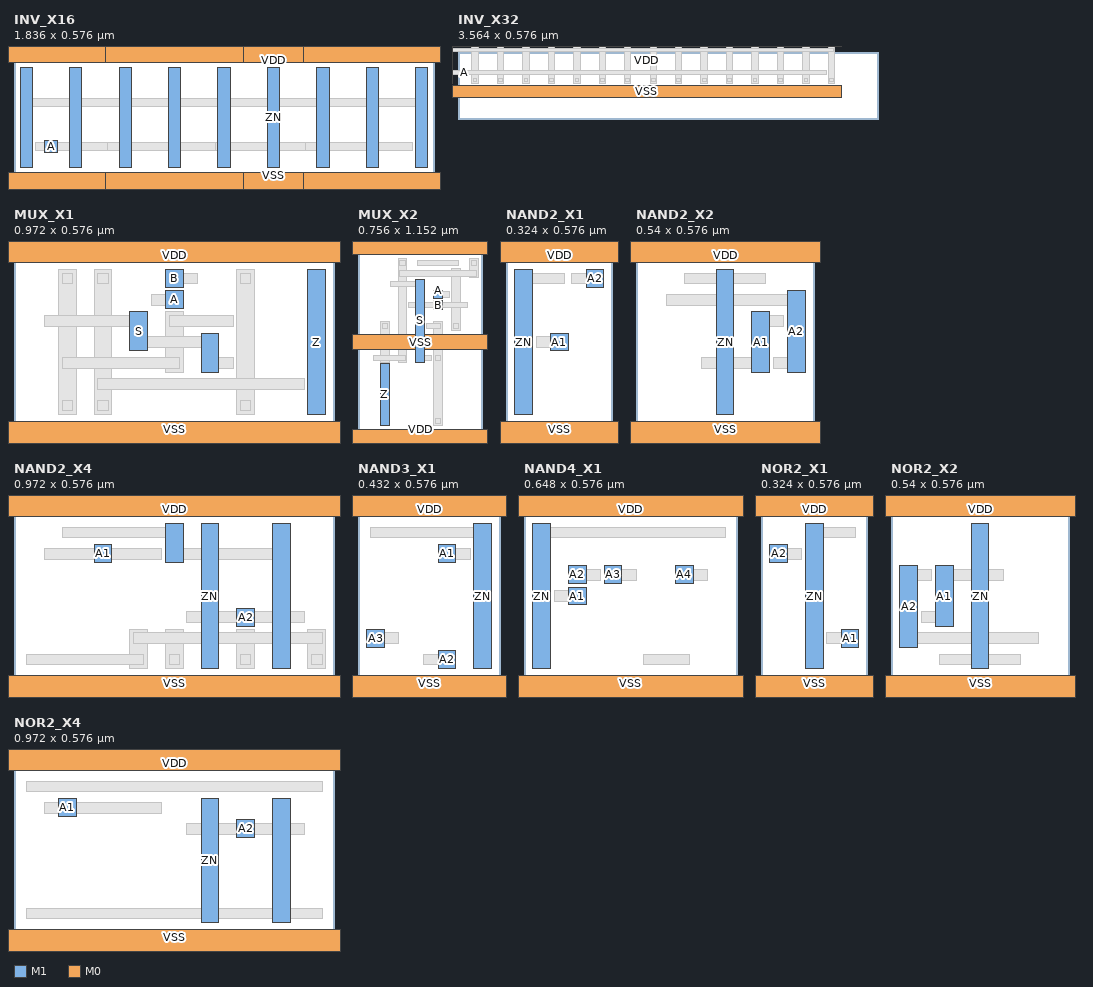
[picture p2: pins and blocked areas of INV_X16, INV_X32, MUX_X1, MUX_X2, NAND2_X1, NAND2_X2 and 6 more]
MACRO INV_X16
  CLASS CORE ;
  FOREIGN INV_X16 0 0 ;
  SIZE 1.836 BY 0.576 ;
  ORIGIN 0.0 0.0 ;
  SYMMETRY X Y ;
  PIN A
    DIRECTION INPUT ;
    USE SIGNAL ;
    ANTENNAGATEAREA 0.084480 ;
    PORT
      LAYER M1 ;
        RECT 0.135 0.133 0.189 0.187 ;
    END
  END A
  PIN ZN
    DIRECTION OUTPUT ;
    USE SIGNAL ;
    ANTENNADIFFAREA 0.18576 ;
    PORT
      LAYER M1 ;
        RECT 0.027 0.069 0.081 0.507 ;
        RECT 0.675 0.069 0.729 0.507 ;
        RECT 0.243 0.069 0.297 0.507 ;
        RECT 1.107 0.069 1.161 0.507 ;
        RECT 0.891 0.069 0.945 0.507 ;
        RECT 0.459 0.069 0.513 0.507 ;
        RECT 1.539 0.069 1.593 0.507 ;
        RECT 1.323 0.069 1.377 0.507 ;
        RECT 1.755 0.069 1.809 0.507 ;
    END
  END ZN
  PIN VDD
    DIRECTION INOUT ;
    USE POWER ;
    PORT
      LAYER M0 ;
        RECT 0.833 0.528 1.435 0.624 ;
        RECT -0.031 0.528 0.571 0.624 ;
        RECT 0.401 0.528 1.003 0.624 ;
        RECT 1.265 0.528 1.867 0.624 ;
    END
  END VDD
  PIN VSS
    DIRECTION INOUT ;
    USE GROUND ;
    PORT
      LAYER M0 ;
        RECT -0.031 -0.048 0.571 0.048 ;
        RECT 0.833 -0.048 1.435 0.048 ;
        RECT 0.401 -0.048 1.003 0.048 ;
        RECT 1.265 -0.048 1.867 0.048 ;
    END
  END VSS
  OBS
    LAYER M0 ;
      RECT 0.851 0.144 1.312 0.176 ;
      RECT 1.273 0.144 1.744 0.176 ;
      RECT 0.092 0.144 0.448 0.176 ;
      RECT 0.409 0.144 0.88 0.176 ;
      RECT 0.47 0.336 0.934 0.368 ;
      RECT 1.334 0.336 1.798 0.368 ;
      RECT 0.038 0.08 0.07 0.112 ;
      RECT 0.902 0.336 1.366 0.368 ;
      RECT 0.038 0.464 0.07 0.496 ;
      RECT 0.038 0.336 0.502 0.368 ;
      RECT 0.47 0.08 0.502 0.112 ;
      RECT 1.55 0.464 1.582 0.496 ;
      RECT 1.766 0.08 1.798 0.112 ;
      RECT 0.47 0.464 0.502 0.496 ;
      RECT 1.118 0.08 1.15 0.112 ;
      RECT 0.686 0.464 0.718 0.496 ;
      RECT 1.334 0.08 1.366 0.112 ;
      RECT 0.254 0.08 0.286 0.112 ;
      RECT 0.902 0.464 0.934 0.496 ;
      RECT 0.686 0.08 0.718 0.112 ;
      RECT 1.766 0.464 1.798 0.496 ;
      RECT 1.55 0.08 1.582 0.112 ;
      RECT 1.334 0.464 1.366 0.496 ;
      RECT 1.118 0.464 1.15 0.496 ;
      RECT 0.902 0.08 0.934 0.112 ;
      RECT 0.254 0.464 0.286 0.496 ;
  END
END INV_X16

MACRO INV_X32
  CLASS CORE ;
  ORIGIN 0 0 ;
  FOREIGN INV_X32 0 0 ;
  SIZE 3.564 BY 0.576 ;
  PIN VDD
    DIRECTION INOUT ;
    USE POWER ;
    PORT
      LAYER M0 ;
        RECT -0.372 0.762 3.254 0.858 ;
    END
  END VDD
  PIN VSS
    DIRECTION INOUT ;
    USE GROUND ;
    PORT
      LAYER M0 ;
        RECT -0.372 0.186 3.254 0.282 ;
    END
  END VSS
  PIN ZN
    DIRECTION INOUT ;
    USE SIGNAL ;
    PORT
      LAYER M1 ;
        RECT -0.314 0.303 -0.26 0.741 ;
    END
  END ZN
  PIN A
    DIRECTION INOUT ;
    USE SIGNAL ;
    PORT
      LAYER M1 ;
        RECT -0.206 0.367 -0.152 0.421 ;
    END
  END A
  OBS
    LAYER M1 SPACING 0 ;
      RECT -0.098 0.303 -0.044 0.741 ;
      RECT 0.118 0.303 0.172 0.741 ;
      RECT 0.334 0.303 0.388 0.741 ;
      RECT 0.55 0.303 0.604 0.741 ;
      RECT 0.766 0.303 0.82 0.741 ;
      RECT 0.982 0.303 1.036 0.741 ;
      RECT 1.198 0.303 1.252 0.741 ;
      RECT 1.414 0.303 1.468 0.741 ;
      RECT 1.63 0.303 1.684 0.741 ;
      RECT 1.846 0.303 1.9 0.741 ;
      RECT 2.062 0.303 2.116 0.741 ;
      RECT 2.278 0.303 2.332 0.741 ;
      RECT 2.494 0.303 2.548 0.741 ;
      RECT 2.71 0.303 2.764 0.741 ;
      RECT 2.926 0.303 2.98 0.741 ;
      RECT 3.142 0.303 3.196 0.741 ;
    LAYER M0 SPACING 0 ;
      RECT -0.303 0.314 -0.271 0.346 ;
      RECT -0.087 0.314 -0.055 0.346 ;
      RECT 0.129 0.314 0.161 0.346 ;
      RECT 0.345 0.314 0.377 0.346 ;
      RECT 0.561 0.314 0.593 0.346 ;
      RECT 0.777 0.314 0.809 0.346 ;
      RECT 0.993 0.314 1.025 0.346 ;
      RECT 1.209 0.314 1.241 0.346 ;
      RECT 1.425 0.314 1.457 0.346 ;
      RECT 1.641 0.314 1.673 0.346 ;
      RECT 1.857 0.314 1.889 0.346 ;
      RECT 2.073 0.314 2.105 0.346 ;
      RECT 2.289 0.314 2.321 0.346 ;
      RECT 2.505 0.314 2.537 0.346 ;
      RECT 2.721 0.314 2.753 0.346 ;
      RECT 2.937 0.314 2.969 0.346 ;
      RECT 3.153 0.314 3.185 0.346 ;
      RECT -0.249 0.378 3.131 0.41 ;
      RECT -0.303 0.57 3.185 0.602 ;
      RECT -0.303 0.698 -0.271 0.73 ;
      RECT -0.087 0.698 -0.055 0.73 ;
      RECT 0.129 0.698 0.161 0.73 ;
      RECT 0.345 0.698 0.377 0.73 ;
      RECT 0.561 0.698 0.593 0.73 ;
      RECT 0.777 0.698 0.809 0.73 ;
      RECT 0.993 0.698 1.025 0.73 ;
      RECT 1.209 0.698 1.241 0.73 ;
      RECT 1.425 0.698 1.457 0.73 ;
      RECT 1.641 0.698 1.673 0.73 ;
      RECT 1.857 0.698 1.889 0.73 ;
      RECT 2.073 0.698 2.105 0.73 ;
      RECT 2.289 0.698 2.321 0.73 ;
      RECT 2.505 0.698 2.537 0.73 ;
      RECT 2.721 0.698 2.753 0.73 ;
      RECT 2.937 0.698 2.969 0.73 ;
      RECT 3.153 0.698 3.185 0.73 ;
  END
END INV_X32




MACRO MUX_X1
  CLASS CORE ;
  FOREIGN MUX_X1 0 0 ;
  SIZE 0.972 BY 0.576 ;
  ORIGIN 0.0 0.0 ;
  SYMMETRY X Y ;
  PIN A
    DIRECTION INPUT ;
    USE SIGNAL ;
    ANTENNAGATEAREA 0.005280 ;
    PORT
      LAYER M1 ;
        RECT 0.459 0.389 0.513 0.443 ;
    END
  END A
  PIN B
    DIRECTION INPUT ;
    USE SIGNAL ;
    ANTENNAGATEAREA 0.005280 ;
    PORT
      LAYER M1 ;
        RECT 0.459 0.453 0.513 0.507 ;
    END
  END B
  PIN S
    DIRECTION INPUT ;
    USE SIGNAL ;
    ANTENNAGATEAREA 0.010560 ;
    PORT
      LAYER M1 ;
        RECT 0.351 0.261 0.405 0.379 ;
        RECT 0.567 0.197 0.621 0.315 ;
    END
  END S
  PIN Z
    DIRECTION OUTPUT ;
    USE SIGNAL ;
    ANTENNADIFFAREA 0.02064 ;
    PORT
      LAYER M1 ;
        RECT 0.891 0.069 0.945 0.507 ;
    END
  END Z
  PIN VDD
    DIRECTION INOUT ;
    USE POWER ;
    PORT
      LAYER M0 ;
        RECT -0.031 0.528 1.003 0.624 ;
    END
  END VDD
  PIN VSS
    DIRECTION INOUT ;
    USE GROUND ;
    PORT
      LAYER M0 ;
        RECT -0.031 -0.048 1.003 0.048 ;
    END
  END VSS
  OBS
    LAYER M1 ;
      RECT 0.243 0.069 0.297 0.507 ;
      RECT 0.675 0.069 0.729 0.507 ;
      RECT 0.135 0.069 0.189 0.507 ;
      RECT 0.459 0.197 0.513 0.379 ;
    LAYER M0 ;
      RECT 0.254 0.144 0.88 0.176 ;
      RECT 0.47 0.336 0.664 0.368 ;
      RECT 0.146 0.208 0.502 0.24 ;
      RECT 0.254 0.464 0.286 0.496 ;
      RECT 0.686 0.464 0.718 0.496 ;
      RECT 0.254 0.08 0.286 0.112 ;
      RECT 0.686 0.08 0.718 0.112 ;
      RECT 0.146 0.464 0.178 0.496 ;
      RECT 0.146 0.08 0.178 0.112 ;
      RECT 0.416 0.4 0.502 0.432 ;
      RECT 0.47 0.464 0.556 0.496 ;
      RECT 0.092 0.336 0.394 0.368 ;
      RECT 0.362 0.272 0.61 0.304 ;
      RECT 0.578 0.208 0.664 0.24 ;
      RECT 0.902 0.464 0.934 0.496 ;
      RECT 0.902 0.08 0.934 0.112 ;
  END
END MUX_X1

MACRO MUX_X2
  CLASS CORE ;
  FOREIGN MUX_X2 0 0 ;
  SIZE 0.756 BY 1.152 ;
  ORIGIN 0.0 0.0 ;
  SYMMETRY X Y ;
  PIN A
    DIRECTION INPUT ;
    USE SIGNAL ;
    ANTENNAGATEAREA 0.005280 ;
    PORT
      LAYER M1 ;
        RECT 0.459 0.837 0.513 0.891 ;
    END
  END A
  PIN B
    DIRECTION INPUT ;
    USE SIGNAL ;
    ANTENNAGATEAREA 0.007920 ;
    PORT
      LAYER M1 ;
        RECT 0.459 0.773 0.513 0.827 ;
    END
  END B
  PIN S
    DIRECTION INPUT ;
    USE SIGNAL ;
    ANTENNAGATEAREA 0.013200 ;
    PORT
      LAYER M1 ;
        RECT 0.351 0.453 0.405 0.955 ;
    END
  END S
  PIN Z
    DIRECTION OUTPUT ;
    USE SIGNAL ;
    ANTENNADIFFAREA 0.02064 ;
    PORT
      LAYER M1 ;
        RECT 0.135 0.069 0.189 0.443 ;
    END
  END Z
  PIN VDD
    DIRECTION INOUT ;
    USE POWER ;
    PORT
      LAYER M0 ;
        RECT -0.031 1.104 0.787 1.2 ;
        RECT -0.031 -0.048 0.787 0.048 ;
    END
  END VDD
  PIN VSS
    DIRECTION INOUT ;
    USE GROUND ;
    PORT
      LAYER M0 ;
        RECT -0.031 0.528 0.787 0.624 ;
    END
  END VSS
  OBS
    LAYER M1 ;
      RECT 0.135 0.453 0.189 0.699 ;
      RECT 0.243 0.453 0.297 1.083 ;
      RECT 0.567 0.645 0.621 1.019 ;
      RECT 0.675 0.965 0.729 1.083 ;
      RECT 0.459 0.069 0.513 0.699 ;
    LAYER M0 ;
      RECT 0.254 0.976 0.718 1.008 ;
      RECT 0.092 0.464 0.286 0.496 ;
      RECT 0.416 0.656 0.502 0.688 ;
      RECT 0.362 1.04 0.61 1.072 ;
      RECT 0.254 1.04 0.286 1.072 ;
      RECT 0.686 1.04 0.718 1.072 ;
      RECT 0.146 0.656 0.178 0.688 ;
      RECT 0.578 0.656 0.61 0.688 ;
      RECT 0.47 0.464 0.502 0.496 ;
      RECT 0.47 0.08 0.502 0.112 ;
      RECT 0.47 0.848 0.556 0.88 ;
      RECT 0.308 0.784 0.664 0.816 ;
      RECT 0.362 0.464 0.448 0.496 ;
      RECT 0.2 0.912 0.394 0.944 ;
      RECT 0.146 0.08 0.178 0.112 ;
      RECT 0.146 0.4 0.178 0.432 ;
  END
END MUX_X2

MACRO NAND2_X1
  CLASS CORE ;
  FOREIGN NAND2_X1 0 0 ;
  SIZE 0.324 BY 0.576 ;
  ORIGIN 0.0 0.0 ;
  SYMMETRY X Y ;
  PIN A1
    DIRECTION INPUT ;
    USE SIGNAL ;
    ANTENNAGATEAREA 0.005280 ;
    PORT
      LAYER M1 ;
        RECT 0.135 0.261 0.189 0.315 ;
    END
  END A1
  PIN A2
    DIRECTION INPUT ;
    USE SIGNAL ;
    ANTENNAGATEAREA 0.005280 ;
    PORT
      LAYER M1 ;
        RECT 0.243 0.453 0.297 0.507 ;
    END
  END A2
  PIN ZN
    DIRECTION OUTPUT ;
    USE SIGNAL ;
    ANTENNADIFFAREA 0.02064 ;
    PORT
      LAYER M1 ;
        RECT 0.027 0.069 0.081 0.507 ;
    END
  END ZN
  PIN VDD
    DIRECTION INOUT ;
    USE POWER ;
    PORT
      LAYER M0 ;
        RECT -0.031 0.528 0.355 0.624 ;
    END
  END VDD
  PIN VSS
    DIRECTION INOUT ;
    USE GROUND ;
    PORT
      LAYER M0 ;
        RECT -0.031 -0.048 0.355 0.048 ;
    END
  END VSS
  OBS
    LAYER M0 ;
      RECT 0.092 0.272 0.178 0.304 ;
      RECT 0.2 0.464 0.286 0.496 ;
      RECT 0.038 0.464 0.178 0.496 ;
      RECT 0.038 0.08 0.07 0.112 ;
  END
END NAND2_X1

MACRO NAND2_X2
  CLASS CORE ;
  FOREIGN NAND2_X2 0 0 ;
  SIZE 0.54 BY 0.576 ;
  ORIGIN 0.0 0.0 ;
  SYMMETRY X Y ;
  PIN A1
    DIRECTION INPUT ;
    USE SIGNAL ;
    ANTENNAGATEAREA 0.010560 ;
    PORT
      LAYER M1 ;
        RECT 0.351 0.197 0.405 0.379 ;
    END
  END A1
  PIN A2
    DIRECTION INPUT ;
    USE SIGNAL ;
    ANTENNAGATEAREA 0.010560 ;
    PORT
      LAYER M1 ;
        RECT 0.459 0.197 0.513 0.443 ;
    END
  END A2
  PIN ZN
    DIRECTION OUTPUT ;
    USE SIGNAL ;
    ANTENNADIFFAREA 0.03096 ;
    PORT
      LAYER M1 ;
        RECT 0.243 0.069 0.297 0.507 ;
    END
  END ZN
  PIN VDD
    DIRECTION INOUT ;
    USE POWER ;
    PORT
      LAYER M0 ;
        RECT -0.031 0.528 0.571 0.624 ;
    END
  END VDD
  PIN VSS
    DIRECTION INOUT ;
    USE GROUND ;
    PORT
      LAYER M0 ;
        RECT -0.031 -0.048 0.571 0.048 ;
    END
  END VSS
  OBS
    LAYER M0 ;
      RECT 0.2 0.208 0.394 0.24 ;
      RECT 0.362 0.336 0.448 0.368 ;
      RECT 0.416 0.208 0.502 0.24 ;
      RECT 0.092 0.4 0.502 0.432 ;
      RECT 0.146 0.464 0.394 0.496 ;
      RECT 0.254 0.08 0.286 0.112 ;
  END
END NAND2_X2

MACRO NAND2_X4
  CLASS CORE ;
  FOREIGN NAND2_X4 0 0 ;
  SIZE 0.972 BY 0.576 ;
  ORIGIN 0.0 0.0 ;
  SYMMETRY X Y ;
  PIN A1
    DIRECTION INPUT ;
    USE SIGNAL ;
    ANTENNAGATEAREA 0.021120 ;
    PORT
      LAYER M1 ;
        RECT 0.243 0.389 0.297 0.443 ;
    END
  END A1
  PIN A2
    DIRECTION INPUT ;
    USE SIGNAL ;
    ANTENNAGATEAREA 0.021120 ;
    PORT
      LAYER M1 ;
        RECT 0.675 0.197 0.729 0.251 ;
    END
  END A2
  PIN ZN
    DIRECTION OUTPUT ;
    USE SIGNAL ;
    ANTENNADIFFAREA 0.06192 ;
    PORT
      LAYER M1 ;
        RECT 0.459 0.389 0.513 0.507 ;
        RECT 0.783 0.069 0.837 0.507 ;
        RECT 0.567 0.069 0.621 0.507 ;
    END
  END ZN
  PIN VDD
    DIRECTION INOUT ;
    USE POWER ;
    PORT
      LAYER M0 ;
        RECT -0.031 0.528 1.003 0.624 ;
    END
  END VDD
  PIN VSS
    DIRECTION INOUT ;
    USE GROUND ;
    PORT
      LAYER M0 ;
        RECT -0.031 -0.048 1.003 0.048 ;
    END
  END VSS
  OBS
    LAYER M1 ;
      RECT 0.351 0.069 0.405 0.187 ;
      RECT 0.459 0.069 0.513 0.187 ;
      RECT 0.675 0.069 0.729 0.187 ;
      RECT 0.891 0.069 0.945 0.187 ;
    LAYER M0 ;
      RECT 0.362 0.144 0.934 0.176 ;
      RECT 0.038 0.08 0.394 0.112 ;
      RECT 0.47 0.08 0.502 0.112 ;
      RECT 0.686 0.08 0.718 0.112 ;
      RECT 0.902 0.08 0.934 0.112 ;
      RECT 0.092 0.4 0.448 0.432 ;
      RECT 0.524 0.208 0.88 0.24 ;
      RECT 0.146 0.464 0.502 0.496 ;
      RECT 0.47 0.4 0.826 0.432 ;
      RECT 0.578 0.464 0.61 0.496 ;
      RECT 0.578 0.08 0.61 0.112 ;
      RECT 0.794 0.464 0.826 0.496 ;
      RECT 0.794 0.08 0.826 0.112 ;
  END
END NAND2_X4

MACRO NAND3_X1
  CLASS CORE ;
  FOREIGN NAND3_X1 0 0 ;
  SIZE 0.432 BY 0.576 ;
  ORIGIN 0.0 0.0 ;
  SYMMETRY X Y ;
  PIN A1
    DIRECTION INPUT ;
    USE SIGNAL ;
    ANTENNAGATEAREA 0.005280 ;
    PORT
      LAYER M1 ;
        RECT 0.243 0.389 0.297 0.443 ;
    END
  END A1
  PIN A2
    DIRECTION INPUT ;
    USE SIGNAL ;
    ANTENNAGATEAREA 0.005280 ;
    PORT
      LAYER M1 ;
        RECT 0.243 0.069 0.297 0.123 ;
    END
  END A2
  PIN A3
    DIRECTION INPUT ;
    USE SIGNAL ;
    ANTENNAGATEAREA 0.005280 ;
    PORT
      LAYER M1 ;
        RECT 0.027 0.133 0.081 0.187 ;
    END
  END A3
  PIN ZN
    DIRECTION OUTPUT ;
    USE SIGNAL ;
    ANTENNADIFFAREA 0.03096 ;
    PORT
      LAYER M1 ;
        RECT 0.351 0.069 0.405 0.507 ;
    END
  END ZN
  PIN VDD
    DIRECTION INOUT ;
    USE POWER ;
    PORT
      LAYER M0 ;
        RECT -0.031 0.528 0.463 0.624 ;
    END
  END VDD
  PIN VSS
    DIRECTION INOUT ;
    USE GROUND ;
    PORT
      LAYER M0 ;
        RECT -0.031 -0.048 0.463 0.048 ;
    END
  END VSS
  OBS
    LAYER M0 ;
      RECT 0.254 0.4 0.34 0.432 ;
      RECT 0.2 0.08 0.286 0.112 ;
      RECT 0.038 0.144 0.124 0.176 ;
      RECT 0.362 0.08 0.394 0.112 ;
      RECT 0.038 0.464 0.394 0.496 ;
  END
END NAND3_X1

MACRO NAND4_X1
  CLASS CORE ;
  FOREIGN NAND4_X1 0 0 ;
  SIZE 0.648 BY 0.576 ;
  ORIGIN 0.0 0.0 ;
  SYMMETRY X Y ;
  PIN A1
    DIRECTION INPUT ;
    USE SIGNAL ;
    ANTENNAGATEAREA 0.005280 ;
    PORT
      LAYER M1 ;
        RECT 0.135 0.261 0.189 0.315 ;
    END
  END A1
  PIN A2
    DIRECTION INPUT ;
    USE SIGNAL ;
    ANTENNAGATEAREA 0.005280 ;
    PORT
      LAYER M1 ;
        RECT 0.135 0.325 0.189 0.379 ;
    END
  END A2
  PIN A3
    DIRECTION INPUT ;
    USE SIGNAL ;
    ANTENNAGATEAREA 0.005280 ;
    PORT
      LAYER M1 ;
        RECT 0.243 0.325 0.297 0.379 ;
    END
  END A3
  PIN A4
    DIRECTION INPUT ;
    USE SIGNAL ;
    ANTENNAGATEAREA 0.005280 ;
    PORT
      LAYER M1 ;
        RECT 0.459 0.325 0.513 0.379 ;
    END
  END A4
  PIN ZN
    DIRECTION OUTPUT ;
    USE SIGNAL ;
    ANTENNADIFFAREA 0.04128 ;
    PORT
      LAYER M1 ;
        RECT 0.027 0.069 0.081 0.507 ;
    END
  END ZN
  PIN VDD
    DIRECTION INOUT ;
    USE POWER ;
    PORT
      LAYER M0 ;
        RECT -0.031 0.528 0.679 0.624 ;
    END
  END VDD
  PIN VSS
    DIRECTION INOUT ;
    USE GROUND ;
    PORT
      LAYER M0 ;
        RECT -0.031 -0.048 0.679 0.048 ;
    END
  END VSS
  OBS
    LAYER M0 ;
      RECT 0.362 0.08 0.502 0.112 ;
      RECT 0.092 0.272 0.178 0.304 ;
      RECT 0.146 0.336 0.232 0.368 ;
      RECT 0.254 0.336 0.34 0.368 ;
      RECT 0.47 0.336 0.556 0.368 ;
      RECT 0.038 0.08 0.07 0.112 ;
      RECT 0.038 0.464 0.61 0.496 ;
  END
END NAND4_X1

MACRO NOR2_X1
  CLASS CORE ;
  FOREIGN NOR2_X1 0 0 ;
  SIZE 0.324 BY 0.576 ;
  ORIGIN 0.0 0.0 ;
  SYMMETRY X Y ;
  PIN A1
    DIRECTION INPUT ;
    USE SIGNAL ;
    ANTENNAGATEAREA 0.005280 ;
    PORT
      LAYER M1 ;
        RECT 0.243 0.133 0.297 0.187 ;
    END
  END A1
  PIN A2
    DIRECTION INPUT ;
    USE SIGNAL ;
    ANTENNAGATEAREA 0.005280 ;
    PORT
      LAYER M1 ;
        RECT 0.027 0.389 0.081 0.443 ;
    END
  END A2
  PIN ZN
    DIRECTION OUTPUT ;
    USE SIGNAL ;
    ANTENNADIFFAREA 0.02064 ;
    PORT
      LAYER M1 ;
        RECT 0.135 0.069 0.189 0.507 ;
    END
  END ZN
  PIN VDD
    DIRECTION INOUT ;
    USE POWER ;
    PORT
      LAYER M0 ;
        RECT -0.031 0.528 0.355 0.624 ;
    END
  END VDD
  PIN VSS
    DIRECTION INOUT ;
    USE GROUND ;
    PORT
      LAYER M0 ;
        RECT -0.031 -0.048 0.355 0.048 ;
    END
  END VSS
  OBS
    LAYER M0 ;
      RECT 0.2 0.144 0.286 0.176 ;
      RECT 0.038 0.4 0.124 0.432 ;
      RECT 0.146 0.464 0.286 0.496 ;
      RECT 0.146 0.08 0.178 0.112 ;
  END
END NOR2_X1

MACRO NOR2_X2
  CLASS CORE ;
  FOREIGN NOR2_X2 0 0 ;
  SIZE 0.54 BY 0.576 ;
  ORIGIN 0.0 0.0 ;
  SYMMETRY X Y ;
  PIN A1
    DIRECTION INPUT ;
    USE SIGNAL ;
    ANTENNAGATEAREA 0.010560 ;
    PORT
      LAYER M1 ;
        RECT 0.135 0.197 0.189 0.379 ;
    END
  END A1
  PIN A2
    DIRECTION INPUT ;
    USE SIGNAL ;
    ANTENNAGATEAREA 0.010560 ;
    PORT
      LAYER M1 ;
        RECT 0.027 0.133 0.081 0.379 ;
    END
  END A2
  PIN ZN
    DIRECTION OUTPUT ;
    USE SIGNAL ;
    ANTENNADIFFAREA 0.03096 ;
    PORT
      LAYER M1 ;
        RECT 0.243 0.069 0.297 0.507 ;
    END
  END ZN
  PIN VDD
    DIRECTION INOUT ;
    USE POWER ;
    PORT
      LAYER M0 ;
        RECT -0.031 0.528 0.571 0.624 ;
    END
  END VDD
  PIN VSS
    DIRECTION INOUT ;
    USE GROUND ;
    PORT
      LAYER M0 ;
        RECT -0.031 -0.048 0.571 0.048 ;
    END
  END VSS
  OBS
    LAYER M0 ;
      RECT 0.146 0.336 0.34 0.368 ;
      RECT 0.092 0.208 0.178 0.24 ;
      RECT 0.038 0.144 0.448 0.176 ;
      RECT 0.038 0.336 0.124 0.368 ;
      RECT 0.254 0.464 0.286 0.496 ;
      RECT 0.146 0.08 0.394 0.112 ;
  END
END NOR2_X2

MACRO NOR2_X4
  CLASS CORE ;
  FOREIGN NOR2_X4 0 0 ;
  SIZE 0.972 BY 0.576 ;
  ORIGIN 0.0 0.0 ;
  SYMMETRY X Y ;
  PIN A1
    DIRECTION INPUT ;
    USE SIGNAL ;
    ANTENNAGATEAREA 0.021120 ;
    PORT
      LAYER M1 ;
        RECT 0.135 0.389 0.189 0.443 ;
    END
  END A1
  PIN A2
    DIRECTION INPUT ;
    USE SIGNAL ;
    ANTENNAGATEAREA 0.021120 ;
    PORT
      LAYER M1 ;
        RECT 0.675 0.325 0.729 0.379 ;
    END
  END A2
  PIN ZN
    DIRECTION OUTPUT ;
    USE SIGNAL ;
    ANTENNADIFFAREA 0.07224 ;
    PORT
      LAYER M1 ;
        RECT 0.567 0.069 0.621 0.443 ;
        RECT 0.783 0.069 0.837 0.443 ;
    END
  END ZN
  PIN VDD
    DIRECTION INOUT ;
    USE POWER ;
    PORT
      LAYER M0 ;
        RECT -0.031 0.528 1.003 0.624 ;
    END
  END VDD
  PIN VSS
    DIRECTION INOUT ;
    USE GROUND ;
    PORT
      LAYER M0 ;
        RECT -0.031 -0.048 1.003 0.048 ;
    END
  END VSS
  OBS
    LAYER M0 ;
      RECT 0.038 0.464 0.934 0.496 ;
      RECT 0.092 0.4 0.448 0.432 ;
      RECT 0.524 0.336 0.88 0.368 ;
      RECT 0.038 0.08 0.934 0.112 ;
      RECT 0.578 0.4 0.61 0.432 ;
      RECT 0.794 0.4 0.826 0.432 ;
  END
END NOR2_X4

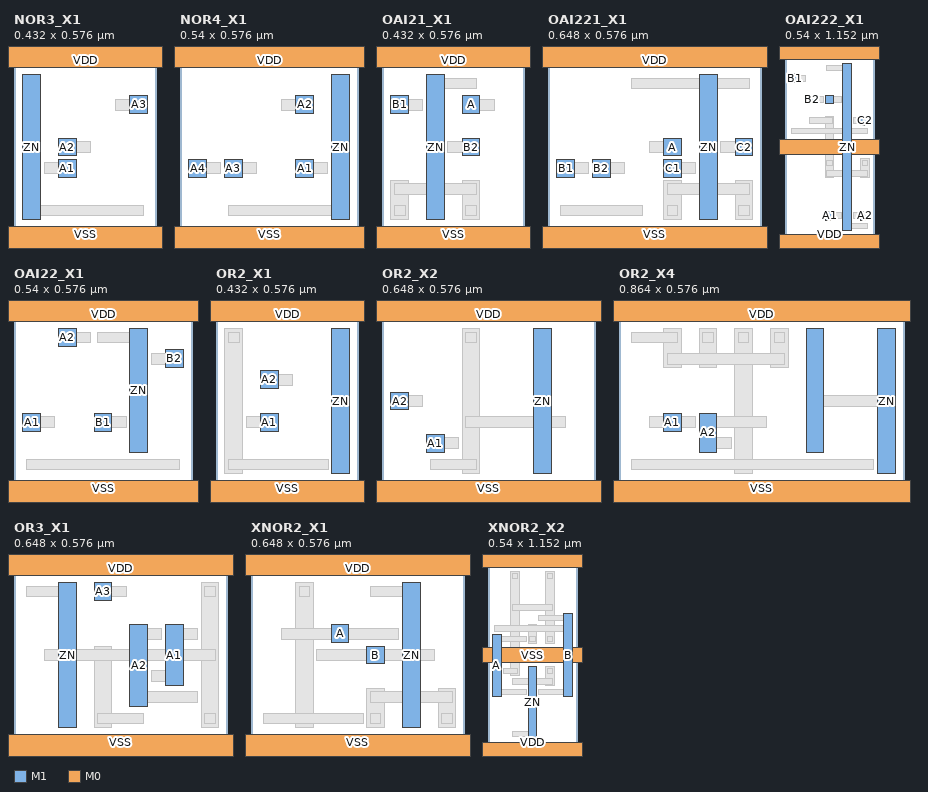
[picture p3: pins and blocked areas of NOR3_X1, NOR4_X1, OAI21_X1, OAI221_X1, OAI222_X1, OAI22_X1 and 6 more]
MACRO NOR3_X1
  CLASS CORE ;
  FOREIGN NOR3_X1 0 0 ;
  SIZE 0.432 BY 0.576 ;
  ORIGIN 0.0 0.0 ;
  SYMMETRY X Y ;
  PIN A1
    DIRECTION INPUT ;
    USE SIGNAL ;
    ANTENNAGATEAREA 0.005280 ;
    PORT
      LAYER M1 ;
        RECT 0.135 0.197 0.189 0.251 ;
    END
  END A1
  PIN A2
    DIRECTION INPUT ;
    USE SIGNAL ;
    ANTENNAGATEAREA 0.005280 ;
    PORT
      LAYER M1 ;
        RECT 0.135 0.261 0.189 0.315 ;
    END
  END A2
  PIN A3
    DIRECTION INPUT ;
    USE SIGNAL ;
    ANTENNAGATEAREA 0.005280 ;
    PORT
      LAYER M1 ;
        RECT 0.351 0.389 0.405 0.443 ;
    END
  END A3
  PIN ZN
    DIRECTION OUTPUT ;
    USE SIGNAL ;
    ANTENNADIFFAREA 0.03096 ;
    PORT
      LAYER M1 ;
        RECT 0.027 0.069 0.081 0.507 ;
    END
  END ZN
  PIN VDD
    DIRECTION INOUT ;
    USE POWER ;
    PORT
      LAYER M0 ;
        RECT -0.031 0.528 0.463 0.624 ;
    END
  END VDD
  PIN VSS
    DIRECTION INOUT ;
    USE GROUND ;
    PORT
      LAYER M0 ;
        RECT -0.031 -0.048 0.463 0.048 ;
    END
  END VSS
  OBS
    LAYER M0 ;
      RECT 0.092 0.208 0.178 0.24 ;
      RECT 0.146 0.272 0.232 0.304 ;
      RECT 0.308 0.4 0.394 0.432 ;
      RECT 0.038 0.08 0.394 0.112 ;
      RECT 0.038 0.464 0.07 0.496 ;
  END
END NOR3_X1

MACRO NOR4_X1
  CLASS CORE ;
  FOREIGN NOR4_X1 0 0 ;
  SIZE 0.54 BY 0.576 ;
  ORIGIN 0.0 0.0 ;
  SYMMETRY X Y ;
  PIN A1
    DIRECTION INPUT ;
    USE SIGNAL ;
    ANTENNAGATEAREA 0.005280 ;
    PORT
      LAYER M1 ;
        RECT 0.351 0.197 0.405 0.251 ;
    END
  END A1
  PIN A2
    DIRECTION INPUT ;
    USE SIGNAL ;
    ANTENNAGATEAREA 0.005280 ;
    PORT
      LAYER M1 ;
        RECT 0.351 0.389 0.405 0.443 ;
    END
  END A2
  PIN A3
    DIRECTION INPUT ;
    USE SIGNAL ;
    ANTENNAGATEAREA 0.005280 ;
    PORT
      LAYER M1 ;
        RECT 0.135 0.197 0.189 0.251 ;
    END
  END A3
  PIN A4
    DIRECTION INPUT ;
    USE SIGNAL ;
    ANTENNAGATEAREA 0.005280 ;
    PORT
      LAYER M1 ;
        RECT 0.027 0.197 0.081 0.251 ;
    END
  END A4
  PIN ZN
    DIRECTION OUTPUT ;
    USE SIGNAL ;
    ANTENNADIFFAREA 0.03096 ;
    PORT
      LAYER M1 ;
        RECT 0.459 0.069 0.513 0.507 ;
    END
  END ZN
  PIN VDD
    DIRECTION INOUT ;
    USE POWER ;
    PORT
      LAYER M0 ;
        RECT -0.031 0.528 0.571 0.624 ;
    END
  END VDD
  PIN VSS
    DIRECTION INOUT ;
    USE GROUND ;
    PORT
      LAYER M0 ;
        RECT -0.031 -0.048 0.571 0.048 ;
    END
  END VSS
  OBS
    LAYER M0 ;
      RECT 0.362 0.208 0.448 0.24 ;
      RECT 0.308 0.4 0.394 0.432 ;
      RECT 0.146 0.208 0.232 0.24 ;
      RECT 0.038 0.208 0.124 0.24 ;
      RECT 0.47 0.464 0.502 0.496 ;
      RECT 0.146 0.08 0.502 0.112 ;
  END
END NOR4_X1

MACRO OAI21_X1
  CLASS CORE ;
  FOREIGN OAI21_X1 0 0 ;
  SIZE 0.432 BY 0.576 ;
  ORIGIN 0.0 0.0 ;
  SYMMETRY X Y ;
  PIN A
    DIRECTION INPUT ;
    USE SIGNAL ;
    ANTENNAGATEAREA 0.005280 ;
    PORT
      LAYER M1 ;
        RECT 0.243 0.389 0.297 0.443 ;
    END
  END A
  PIN B1
    DIRECTION INPUT ;
    USE SIGNAL ;
    ANTENNAGATEAREA 0.005280 ;
    PORT
      LAYER M1 ;
        RECT 0.027 0.389 0.081 0.443 ;
    END
  END B1
  PIN B2
    DIRECTION INPUT ;
    USE SIGNAL ;
    ANTENNAGATEAREA 0.005280 ;
    PORT
      LAYER M1 ;
        RECT 0.243 0.261 0.297 0.315 ;
    END
  END B2
  PIN ZN
    DIRECTION OUTPUT ;
    USE SIGNAL ;
    ANTENNADIFFAREA 0.02064 ;
    PORT
      LAYER M1 ;
        RECT 0.135 0.069 0.189 0.507 ;
    END
  END ZN
  PIN VDD
    DIRECTION INOUT ;
    USE POWER ;
    PORT
      LAYER M0 ;
        RECT -0.031 0.528 0.463 0.624 ;
    END
  END VDD
  PIN VSS
    DIRECTION INOUT ;
    USE GROUND ;
    PORT
      LAYER M0 ;
        RECT -0.031 -0.048 0.463 0.048 ;
    END
  END VSS
  OBS
    LAYER M1 ;
      RECT 0.027 0.069 0.081 0.187 ;
      RECT 0.243 0.069 0.297 0.187 ;
    LAYER M0 ;
      RECT 0.038 0.144 0.286 0.176 ;
      RECT 0.038 0.08 0.07 0.112 ;
      RECT 0.254 0.08 0.286 0.112 ;
      RECT 0.254 0.4 0.34 0.432 ;
      RECT 0.038 0.4 0.124 0.432 ;
      RECT 0.2 0.272 0.286 0.304 ;
      RECT 0.146 0.464 0.286 0.496 ;
      RECT 0.146 0.08 0.178 0.112 ;
  END
END OAI21_X1

MACRO OAI221_X1
  CLASS CORE ;
  FOREIGN OAI221_X1 0 0 ;
  SIZE 0.648 BY 0.576 ;
  ORIGIN 0.0 0.0 ;
  SYMMETRY X Y ;
  PIN A
    DIRECTION INPUT ;
    USE SIGNAL ;
    ANTENNAGATEAREA 0.005280 ;
    PORT
      LAYER M1 ;
        RECT 0.351 0.261 0.405 0.315 ;
    END
  END A
  PIN B1
    DIRECTION INPUT ;
    USE SIGNAL ;
    ANTENNAGATEAREA 0.005280 ;
    PORT
      LAYER M1 ;
        RECT 0.027 0.197 0.081 0.251 ;
    END
  END B1
  PIN B2
    DIRECTION INPUT ;
    USE SIGNAL ;
    ANTENNAGATEAREA 0.005280 ;
    PORT
      LAYER M1 ;
        RECT 0.135 0.197 0.189 0.251 ;
    END
  END B2
  PIN C1
    DIRECTION INPUT ;
    USE SIGNAL ;
    ANTENNAGATEAREA 0.005280 ;
    PORT
      LAYER M1 ;
        RECT 0.351 0.197 0.405 0.251 ;
    END
  END C1
  PIN C2
    DIRECTION INPUT ;
    USE SIGNAL ;
    ANTENNAGATEAREA 0.005280 ;
    PORT
      LAYER M1 ;
        RECT 0.567 0.261 0.621 0.315 ;
    END
  END C2
  PIN ZN
    DIRECTION OUTPUT ;
    USE SIGNAL ;
    ANTENNADIFFAREA 0.03096 ;
    PORT
      LAYER M1 ;
        RECT 0.459 0.069 0.513 0.507 ;
    END
  END ZN
  PIN VDD
    DIRECTION INOUT ;
    USE POWER ;
    PORT
      LAYER M0 ;
        RECT -0.031 0.528 0.679 0.624 ;
    END
  END VDD
  PIN VSS
    DIRECTION INOUT ;
    USE GROUND ;
    PORT
      LAYER M0 ;
        RECT -0.031 -0.048 0.679 0.048 ;
    END
  END VSS
  OBS
    LAYER M1 ;
      RECT 0.351 0.069 0.405 0.187 ;
      RECT 0.567 0.069 0.621 0.187 ;
    LAYER M0 ;
      RECT 0.038 0.08 0.286 0.112 ;
      RECT 0.362 0.144 0.61 0.176 ;
      RECT 0.362 0.08 0.394 0.112 ;
      RECT 0.578 0.08 0.61 0.112 ;
      RECT 0.308 0.272 0.394 0.304 ;
      RECT 0.038 0.208 0.124 0.24 ;
      RECT 0.146 0.208 0.232 0.24 ;
      RECT 0.362 0.208 0.448 0.24 ;
      RECT 0.524 0.272 0.61 0.304 ;
      RECT 0.47 0.08 0.502 0.112 ;
      RECT 0.254 0.464 0.61 0.496 ;
  END
END OAI221_X1

MACRO OAI222_X1
  CLASS CORE ;
  FOREIGN OAI222_X1 0 0 ;
  SIZE 0.54 BY 1.152 ;
  ORIGIN 0.0 0.0 ;
  SYMMETRY X Y ;
  PIN A1
    DIRECTION INPUT ;
    USE SIGNAL ;
    ANTENNAGATEAREA 0.005280 ;
    PORT
      LAYER M1 ;
        RECT 0.243 0.133 0.297 0.187 ;
    END
  END A1
  PIN A2
    DIRECTION INPUT ;
    USE SIGNAL ;
    ANTENNAGATEAREA 0.005280 ;
    PORT
      LAYER M1 ;
        RECT 0.459 0.133 0.513 0.187 ;
    END
  END A2
  PIN B1
    DIRECTION INPUT ;
    USE SIGNAL ;
    ANTENNAGATEAREA 0.005280 ;
    PORT
      LAYER M1 ;
        RECT 0.027 0.965 0.081 1.019 ;
    END
  END B1
  PIN B2
    DIRECTION INPUT ;
    USE SIGNAL ;
    ANTENNAGATEAREA 0.005280 ;
    PORT
      LAYER M1 ;
        RECT 0.135 0.837 0.189 0.891 ;
    END
  END B2
  PIN C1
    DIRECTION INPUT ;
    USE SIGNAL ;
    ANTENNAGATEAREA 0.005280 ;
    PORT
      LAYER M1 ;
        RECT 0.243 0.837 0.297 0.891 ;
    END
  END C1
  PIN C2
    DIRECTION INPUT ;
    USE SIGNAL ;
    ANTENNAGATEAREA 0.005280 ;
    PORT
      LAYER M1 ;
        RECT 0.459 0.709 0.513 0.763 ;
    END
  END C2
  PIN ZN
    DIRECTION OUTPUT ;
    USE SIGNAL ;
    ANTENNADIFFAREA 0.03096 ;
    PORT
      LAYER M1 ;
        RECT 0.351 0.069 0.405 1.083 ;
    END
  END ZN
  PIN VDD
    DIRECTION INOUT ;
    USE POWER ;
    PORT
      LAYER M0 ;
        RECT -0.031 -0.048 0.571 0.048 ;
        RECT -0.031 1.104 0.571 1.2 ;
    END
  END VDD
  PIN VSS
    DIRECTION INOUT ;
    USE GROUND ;
    PORT
      LAYER M0 ;
        RECT -0.031 0.528 0.571 0.624 ;
    END
  END VSS
  OBS
    LAYER M1 ;
      RECT 0.459 0.389 0.513 0.507 ;
      RECT 0.243 0.389 0.297 0.763 ;
    LAYER M0 ;
      RECT 0.47 0.464 0.502 0.496 ;
      RECT 0.254 0.464 0.286 0.496 ;
      RECT 0.254 0.4 0.502 0.432 ;
      RECT 0.146 0.72 0.286 0.752 ;
      RECT 0.038 0.656 0.502 0.688 ;
      RECT 0.254 0.144 0.34 0.176 ;
      RECT 0.416 0.144 0.502 0.176 ;
      RECT 0.038 0.976 0.124 1.008 ;
      RECT 0.146 0.848 0.232 0.88 ;
      RECT 0.254 0.848 0.34 0.88 ;
      RECT 0.416 0.72 0.502 0.752 ;
      RECT 0.362 0.464 0.394 0.496 ;
      RECT 0.254 1.04 0.394 1.072 ;
      RECT 0.362 0.08 0.502 0.112 ;
  END
END OAI222_X1

MACRO OAI22_X1
  CLASS CORE ;
  FOREIGN OAI22_X1 0 0 ;
  SIZE 0.54 BY 0.576 ;
  ORIGIN 0.0 0.0 ;
  SYMMETRY X Y ;
  PIN A1
    DIRECTION INPUT ;
    USE SIGNAL ;
    ANTENNAGATEAREA 0.005280 ;
    PORT
      LAYER M1 ;
        RECT 0.027 0.197 0.081 0.251 ;
    END
  END A1
  PIN A2
    DIRECTION INPUT ;
    USE SIGNAL ;
    ANTENNAGATEAREA 0.005280 ;
    PORT
      LAYER M1 ;
        RECT 0.135 0.453 0.189 0.507 ;
    END
  END A2
  PIN B1
    DIRECTION INPUT ;
    USE SIGNAL ;
    ANTENNAGATEAREA 0.005280 ;
    PORT
      LAYER M1 ;
        RECT 0.243 0.197 0.297 0.251 ;
    END
  END B1
  PIN B2
    DIRECTION INPUT ;
    USE SIGNAL ;
    ANTENNAGATEAREA 0.005280 ;
    PORT
      LAYER M1 ;
        RECT 0.459 0.389 0.513 0.443 ;
    END
  END B2
  PIN ZN
    DIRECTION OUTPUT ;
    USE SIGNAL ;
    ANTENNADIFFAREA 0.02064 ;
    PORT
      LAYER M1 ;
        RECT 0.351 0.133 0.405 0.507 ;
    END
  END ZN
  PIN VDD
    DIRECTION INOUT ;
    USE POWER ;
    PORT
      LAYER M0 ;
        RECT -0.031 0.528 0.571 0.624 ;
    END
  END VDD
  PIN VSS
    DIRECTION INOUT ;
    USE GROUND ;
    PORT
      LAYER M0 ;
        RECT -0.031 -0.048 0.571 0.048 ;
    END
  END VSS
  OBS
    LAYER M0 ;
      RECT 0.038 0.08 0.502 0.112 ;
      RECT 0.038 0.208 0.124 0.24 ;
      RECT 0.146 0.464 0.232 0.496 ;
      RECT 0.254 0.208 0.34 0.24 ;
      RECT 0.416 0.4 0.502 0.432 ;
      RECT 0.254 0.464 0.394 0.496 ;
      RECT 0.362 0.144 0.394 0.176 ;
  END
END OAI22_X1

MACRO OR2_X1
  CLASS CORE ;
  FOREIGN OR2_X1 0 0 ;
  SIZE 0.432 BY 0.576 ;
  ORIGIN 0.0 0.0 ;
  SYMMETRY X Y ;
  PIN A1
    DIRECTION INPUT ;
    USE SIGNAL ;
    ANTENNAGATEAREA 0.005280 ;
    PORT
      LAYER M1 ;
        RECT 0.135 0.197 0.189 0.251 ;
    END
  END A1
  PIN A2
    DIRECTION INPUT ;
    USE SIGNAL ;
    ANTENNAGATEAREA 0.005280 ;
    PORT
      LAYER M1 ;
        RECT 0.135 0.325 0.189 0.379 ;
    END
  END A2
  PIN ZN
    DIRECTION OUTPUT ;
    USE SIGNAL ;
    ANTENNADIFFAREA 0.02064 ;
    PORT
      LAYER M1 ;
        RECT 0.351 0.069 0.405 0.507 ;
    END
  END ZN
  PIN VDD
    DIRECTION INOUT ;
    USE POWER ;
    PORT
      LAYER M0 ;
        RECT -0.031 0.528 0.463 0.624 ;
    END
  END VDD
  PIN VSS
    DIRECTION INOUT ;
    USE GROUND ;
    PORT
      LAYER M0 ;
        RECT -0.031 -0.048 0.463 0.048 ;
    END
  END VSS
  OBS
    LAYER M1 ;
      RECT 0.027 0.069 0.081 0.507 ;
    LAYER M0 ;
      RECT 0.038 0.08 0.34 0.112 ;
      RECT 0.038 0.464 0.07 0.496 ;
      RECT 0.092 0.208 0.178 0.24 ;
      RECT 0.146 0.336 0.232 0.368 ;
      RECT 0.362 0.08 0.394 0.112 ;
      RECT 0.362 0.464 0.394 0.496 ;
  END
END OR2_X1

MACRO OR2_X2
  CLASS CORE ;
  FOREIGN OR2_X2 0 0 ;
  SIZE 0.648 BY 0.576 ;
  ORIGIN 0.0 0.0 ;
  SYMMETRY X Y ;
  PIN A1
    DIRECTION INPUT ;
    USE SIGNAL ;
    ANTENNAGATEAREA 0.005280 ;
    PORT
      LAYER M1 ;
        RECT 0.135 0.133 0.189 0.187 ;
    END
  END A1
  PIN A2
    DIRECTION INPUT ;
    USE SIGNAL ;
    ANTENNAGATEAREA 0.005280 ;
    PORT
      LAYER M1 ;
        RECT 0.027 0.261 0.081 0.315 ;
    END
  END A2
  PIN ZN
    DIRECTION OUTPUT ;
    USE SIGNAL ;
    ANTENNADIFFAREA 0.02064 ;
    PORT
      LAYER M1 ;
        RECT 0.459 0.069 0.513 0.507 ;
    END
  END ZN
  PIN VDD
    DIRECTION INOUT ;
    USE POWER ;
    PORT
      LAYER M0 ;
        RECT -0.031 0.528 0.679 0.624 ;
    END
  END VDD
  PIN VSS
    DIRECTION INOUT ;
    USE GROUND ;
    PORT
      LAYER M0 ;
        RECT -0.031 -0.048 0.679 0.048 ;
    END
  END VSS
  OBS
    LAYER M1 ;
      RECT 0.243 0.069 0.297 0.507 ;
    LAYER M0 ;
      RECT 0.254 0.208 0.556 0.24 ;
      RECT 0.146 0.08 0.286 0.112 ;
      RECT 0.254 0.464 0.286 0.496 ;
      RECT 0.146 0.144 0.232 0.176 ;
      RECT 0.038 0.272 0.124 0.304 ;
      RECT 0.47 0.464 0.502 0.496 ;
      RECT 0.47 0.08 0.502 0.112 ;
  END
END OR2_X2

MACRO OR2_X4
  CLASS CORE ;
  FOREIGN OR2_X4 0 0 ;
  SIZE 0.864 BY 0.576 ;
  ORIGIN 0.0 0.0 ;
  SYMMETRY X Y ;
  PIN A1
    DIRECTION INPUT ;
    USE SIGNAL ;
    ANTENNAGATEAREA 0.010560 ;
    PORT
      LAYER M1 ;
        RECT 0.135 0.197 0.189 0.251 ;
    END
  END A1
  PIN A2
    DIRECTION INPUT ;
    USE SIGNAL ;
    ANTENNAGATEAREA 0.010560 ;
    PORT
      LAYER M1 ;
        RECT 0.243 0.133 0.297 0.251 ;
    END
  END A2
  PIN ZN
    DIRECTION OUTPUT ;
    USE SIGNAL ;
    ANTENNADIFFAREA 0.04128 ;
    PORT
      LAYER M1 ;
        RECT 0.567 0.133 0.621 0.507 ;
        RECT 0.783 0.069 0.837 0.507 ;
    END
  END ZN
  PIN VDD
    DIRECTION INOUT ;
    USE POWER ;
    PORT
      LAYER M0 ;
        RECT -0.031 0.528 0.895 0.624 ;
    END
  END VDD
  PIN VSS
    DIRECTION INOUT ;
    USE GROUND ;
    PORT
      LAYER M0 ;
        RECT -0.031 -0.048 0.895 0.048 ;
    END
  END VSS
  OBS
    LAYER M1 ;
      RECT 0.351 0.069 0.405 0.507 ;
      RECT 0.135 0.389 0.189 0.507 ;
      RECT 0.243 0.389 0.297 0.507 ;
      RECT 0.459 0.389 0.513 0.507 ;
    LAYER M0 ;
      RECT 0.038 0.08 0.772 0.112 ;
      RECT 0.038 0.464 0.178 0.496 ;
      RECT 0.146 0.4 0.502 0.432 ;
      RECT 0.362 0.464 0.394 0.496 ;
      RECT 0.254 0.464 0.286 0.496 ;
      RECT 0.47 0.464 0.502 0.496 ;
      RECT 0.092 0.208 0.232 0.24 ;
      RECT 0.254 0.208 0.448 0.24 ;
      RECT 0.254 0.144 0.34 0.176 ;
      RECT 0.578 0.464 0.61 0.496 ;
      RECT 0.578 0.144 0.61 0.176 ;
      RECT 0.578 0.272 0.826 0.304 ;
      RECT 0.794 0.464 0.826 0.496 ;
      RECT 0.794 0.08 0.826 0.112 ;
  END
END OR2_X4

MACRO OR3_X1
  CLASS CORE ;
  FOREIGN OR3_X1 0 0 ;
  SIZE 0.648 BY 0.576 ;
  ORIGIN 0.0 0.0 ;
  SYMMETRY X Y ;
  PIN A1
    DIRECTION INPUT ;
    USE SIGNAL ;
    ANTENNAGATEAREA 0.005280 ;
    PORT
      LAYER M1 ;
        RECT 0.459 0.197 0.513 0.379 ;
    END
  END A1
  PIN A2
    DIRECTION INPUT ;
    USE SIGNAL ;
    ANTENNAGATEAREA 0.005280 ;
    PORT
      LAYER M1 ;
        RECT 0.351 0.133 0.405 0.379 ;
    END
  END A2
  PIN A3
    DIRECTION INPUT ;
    USE SIGNAL ;
    ANTENNAGATEAREA 0.005280 ;
    PORT
      LAYER M1 ;
        RECT 0.243 0.453 0.297 0.507 ;
    END
  END A3
  PIN ZN
    DIRECTION OUTPUT ;
    USE SIGNAL ;
    ANTENNADIFFAREA 0.02064 ;
    PORT
      LAYER M1 ;
        RECT 0.135 0.069 0.189 0.507 ;
    END
  END ZN
  PIN VDD
    DIRECTION INOUT ;
    USE POWER ;
    PORT
      LAYER M0 ;
        RECT -0.031 0.528 0.679 0.624 ;
    END
  END VDD
  PIN VSS
    DIRECTION INOUT ;
    USE GROUND ;
    PORT
      LAYER M0 ;
        RECT -0.031 -0.048 0.679 0.048 ;
    END
  END VSS
  OBS
    LAYER M1 ;
      RECT 0.243 0.069 0.297 0.315 ;
      RECT 0.567 0.069 0.621 0.507 ;
    LAYER M0 ;
      RECT 0.092 0.272 0.61 0.304 ;
      RECT 0.254 0.08 0.394 0.112 ;
      RECT 0.578 0.464 0.61 0.496 ;
      RECT 0.578 0.08 0.61 0.112 ;
      RECT 0.416 0.208 0.502 0.24 ;
      RECT 0.47 0.336 0.556 0.368 ;
      RECT 0.362 0.336 0.448 0.368 ;
      RECT 0.362 0.144 0.556 0.176 ;
      RECT 0.254 0.464 0.34 0.496 ;
      RECT 0.038 0.464 0.178 0.496 ;
      RECT 0.146 0.08 0.178 0.112 ;
  END
END OR3_X1

MACRO XNOR2_X1
  CLASS CORE ;
  FOREIGN XNOR2_X1 0 0 ;
  SIZE 0.648 BY 0.576 ;
  ORIGIN 0.0 0.0 ;
  SYMMETRY X Y ;
  PIN A
    DIRECTION INPUT ;
    USE SIGNAL ;
    ANTENNAGATEAREA 0.010560 ;
    PORT
      LAYER M1 ;
        RECT 0.243 0.325 0.297 0.379 ;
    END
  END A
  PIN B
    DIRECTION INPUT ;
    USE SIGNAL ;
    ANTENNAGATEAREA 0.010560 ;
    PORT
      LAYER M1 ;
        RECT 0.351 0.261 0.405 0.315 ;
    END
  END B
  PIN ZN
    DIRECTION OUTPUT ;
    USE SIGNAL ;
    ANTENNADIFFAREA 0.02064 ;
    PORT
      LAYER M1 ;
        RECT 0.459 0.069 0.513 0.507 ;
    END
  END ZN
  PIN VDD
    DIRECTION INOUT ;
    USE POWER ;
    PORT
      LAYER M0 ;
        RECT -0.031 0.528 0.679 0.624 ;
    END
  END VDD
  PIN VSS
    DIRECTION INOUT ;
    USE GROUND ;
    PORT
      LAYER M0 ;
        RECT -0.031 -0.048 0.679 0.048 ;
    END
  END VSS
  OBS
    LAYER M1 ;
      RECT 0.135 0.069 0.189 0.507 ;
      RECT 0.351 0.069 0.405 0.187 ;
      RECT 0.567 0.069 0.621 0.187 ;
    LAYER M0 ;
      RECT 0.038 0.08 0.34 0.112 ;
      RECT 0.362 0.144 0.61 0.176 ;
      RECT 0.146 0.464 0.178 0.496 ;
      RECT 0.362 0.08 0.394 0.112 ;
      RECT 0.578 0.08 0.61 0.112 ;
      RECT 0.092 0.336 0.448 0.368 ;
      RECT 0.2 0.272 0.556 0.304 ;
      RECT 0.362 0.464 0.502 0.496 ;
      RECT 0.47 0.08 0.502 0.112 ;
  END
END XNOR2_X1

MACRO XNOR2_X2
  CLASS CORE ;
  FOREIGN XNOR2_X2 0 0 ;
  SIZE 0.54 BY 1.152 ;
  ORIGIN 0.0 0.0 ;
  SYMMETRY X Y ;
  PIN A
    DIRECTION INPUT ;
    USE SIGNAL ;
    ANTENNAGATEAREA 0.015840 ;
    PORT
      LAYER M1 ;
        RECT 0.027 0.325 0.081 0.699 ;
    END
  END A
  PIN B
    DIRECTION INPUT ;
    USE SIGNAL ;
    ANTENNAGATEAREA 0.015840 ;
    PORT
      LAYER M1 ;
        RECT 0.459 0.325 0.513 0.827 ;
    END
  END B
  PIN ZN
    DIRECTION OUTPUT ;
    USE SIGNAL ;
    ANTENNADIFFAREA 0.02064 ;
    PORT
      LAYER M1 ;
        RECT 0.243 0.069 0.297 0.507 ;
    END
  END ZN
  PIN VDD
    DIRECTION INOUT ;
    USE POWER ;
    PORT
      LAYER M0 ;
        RECT -0.031 1.104 0.571 1.2 ;
        RECT -0.031 -0.048 0.571 0.048 ;
    END
  END VDD
  PIN VSS
    DIRECTION INOUT ;
    USE GROUND ;
    PORT
      LAYER M0 ;
        RECT -0.031 0.528 0.571 0.624 ;
    END
  END VSS
  OBS
    LAYER M1 ;
      RECT 0.135 0.453 0.189 1.083 ;
      RECT 0.351 0.645 0.405 1.083 ;
      RECT 0.351 0.389 0.405 0.507 ;
      RECT 0.243 0.645 0.297 0.763 ;
    LAYER M0 ;
      RECT 0.146 0.848 0.394 0.88 ;
      RECT 0.092 0.464 0.178 0.496 ;
      RECT 0.146 0.4 0.394 0.432 ;
      RECT 0.038 0.72 0.502 0.752 ;
      RECT 0.146 1.04 0.178 1.072 ;
      RECT 0.362 1.04 0.394 1.072 ;
      RECT 0.362 0.656 0.394 0.688 ;
      RECT 0.362 0.464 0.394 0.496 ;
      RECT 0.254 0.656 0.286 0.688 ;
      RECT 0.038 0.656 0.232 0.688 ;
      RECT 0.038 0.336 0.232 0.368 ;
      RECT 0.308 0.784 0.502 0.816 ;
      RECT 0.308 0.336 0.502 0.368 ;
      RECT 0.254 0.464 0.286 0.496 ;
      RECT 0.146 0.08 0.286 0.112 ;
  END
END XNOR2_X2

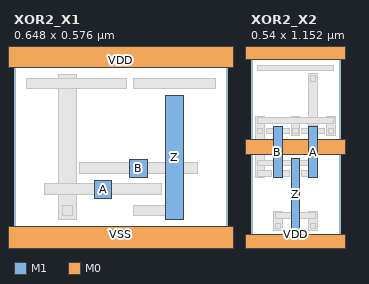
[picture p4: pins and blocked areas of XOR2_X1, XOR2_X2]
MACRO XOR2_X1
  CLASS CORE ;
  FOREIGN XOR2_X1 0 0 ;
  SIZE 0.648 BY 0.576 ;
  ORIGIN 0.0 0.0 ;
  SYMMETRY X Y ;
  PIN A
    DIRECTION INPUT ;
    USE SIGNAL ;
    ANTENNAGATEAREA 0.010560 ;
    PORT
      LAYER M1 ;
        RECT 0.243 0.133 0.297 0.187 ;
    END
  END A
  PIN B
    DIRECTION INPUT ;
    USE SIGNAL ;
    ANTENNAGATEAREA 0.010560 ;
    PORT
      LAYER M1 ;
        RECT 0.351 0.197 0.405 0.251 ;
    END
  END B
  PIN Z
    DIRECTION OUTPUT ;
    USE SIGNAL ;
    ANTENNADIFFAREA 0.02064 ;
    PORT
      LAYER M1 ;
        RECT 0.459 0.069 0.513 0.443 ;
    END
  END Z
  PIN VDD
    DIRECTION INOUT ;
    USE POWER ;
    PORT
      LAYER M0 ;
        RECT -0.031 0.528 0.679 0.624 ;
    END
  END VDD
  PIN VSS
    DIRECTION INOUT ;
    USE GROUND ;
    PORT
      LAYER M0 ;
        RECT -0.031 -0.048 0.679 0.048 ;
    END
  END VSS
  OBS
    LAYER M1 ;
      RECT 0.135 0.069 0.189 0.507 ;
    LAYER M0 ;
      RECT 0.362 0.464 0.61 0.496 ;
      RECT 0.038 0.464 0.34 0.496 ;
      RECT 0.146 0.08 0.178 0.112 ;
      RECT 0.092 0.144 0.448 0.176 ;
      RECT 0.2 0.208 0.556 0.24 ;
      RECT 0.47 0.4 0.502 0.432 ;
      RECT 0.362 0.08 0.502 0.112 ;
  END
END XOR2_X1

MACRO XOR2_X2
  CLASS CORE ;
  FOREIGN XOR2_X2 0 0 ;
  SIZE 0.54 BY 1.152 ;
  ORIGIN 0.0 0.0 ;
  SYMMETRY X Y ;
  PIN A
    DIRECTION INPUT ;
    USE SIGNAL ;
    ANTENNAGATEAREA 0.015840 ;
    PORT
      LAYER M1 ;
        RECT 0.351 0.389 0.405 0.699 ;
    END
  END A
  PIN B
    DIRECTION INPUT ;
    USE SIGNAL ;
    ANTENNAGATEAREA 0.015840 ;
    PORT
      LAYER M1 ;
        RECT 0.135 0.389 0.189 0.699 ;
    END
  END B
  PIN Z
    DIRECTION OUTPUT ;
    USE SIGNAL ;
    ANTENNADIFFAREA 0.03096 ;
    PORT
      LAYER M1 ;
        RECT 0.243 0.069 0.297 0.507 ;
    END
  END Z
  PIN VDD
    DIRECTION INOUT ;
    USE POWER ;
    PORT
      LAYER M0 ;
        RECT -0.031 1.104 0.571 1.2 ;
        RECT -0.031 -0.048 0.571 0.048 ;
    END
  END VDD
  PIN VSS
    DIRECTION INOUT ;
    USE GROUND ;
    PORT
      LAYER M0 ;
        RECT -0.031 0.528 0.571 0.624 ;
    END
  END VSS
  OBS
    LAYER M1 ;
      RECT 0.027 0.389 0.081 0.763 ;
      RECT 0.243 0.645 0.297 0.763 ;
      RECT 0.351 0.709 0.405 1.019 ;
      RECT 0.459 0.645 0.513 0.763 ;
      RECT 0.135 0.069 0.189 0.187 ;
      RECT 0.351 0.069 0.405 0.187 ;
    LAYER M0 ;
      RECT 0.038 1.04 0.502 1.072 ;
      RECT 0.038 0.72 0.502 0.752 ;
      RECT 0.038 0.4 0.124 0.432 ;
      RECT 0.146 0.144 0.394 0.176 ;
      RECT 0.362 0.976 0.394 1.008 ;
      RECT 0.038 0.656 0.07 0.688 ;
      RECT 0.254 0.656 0.286 0.688 ;
      RECT 0.47 0.656 0.502 0.688 ;
      RECT 0.146 0.08 0.178 0.112 ;
      RECT 0.362 0.08 0.394 0.112 ;
      RECT 0.308 0.656 0.448 0.688 ;
      RECT 0.308 0.4 0.394 0.432 ;
      RECT 0.146 0.4 0.232 0.432 ;
      RECT 0.092 0.656 0.232 0.688 ;
      RECT 0.038 0.464 0.394 0.496 ;
      RECT 0.254 0.08 0.286 0.112 ;
  END
END XOR2_X2

END LIBRARY
